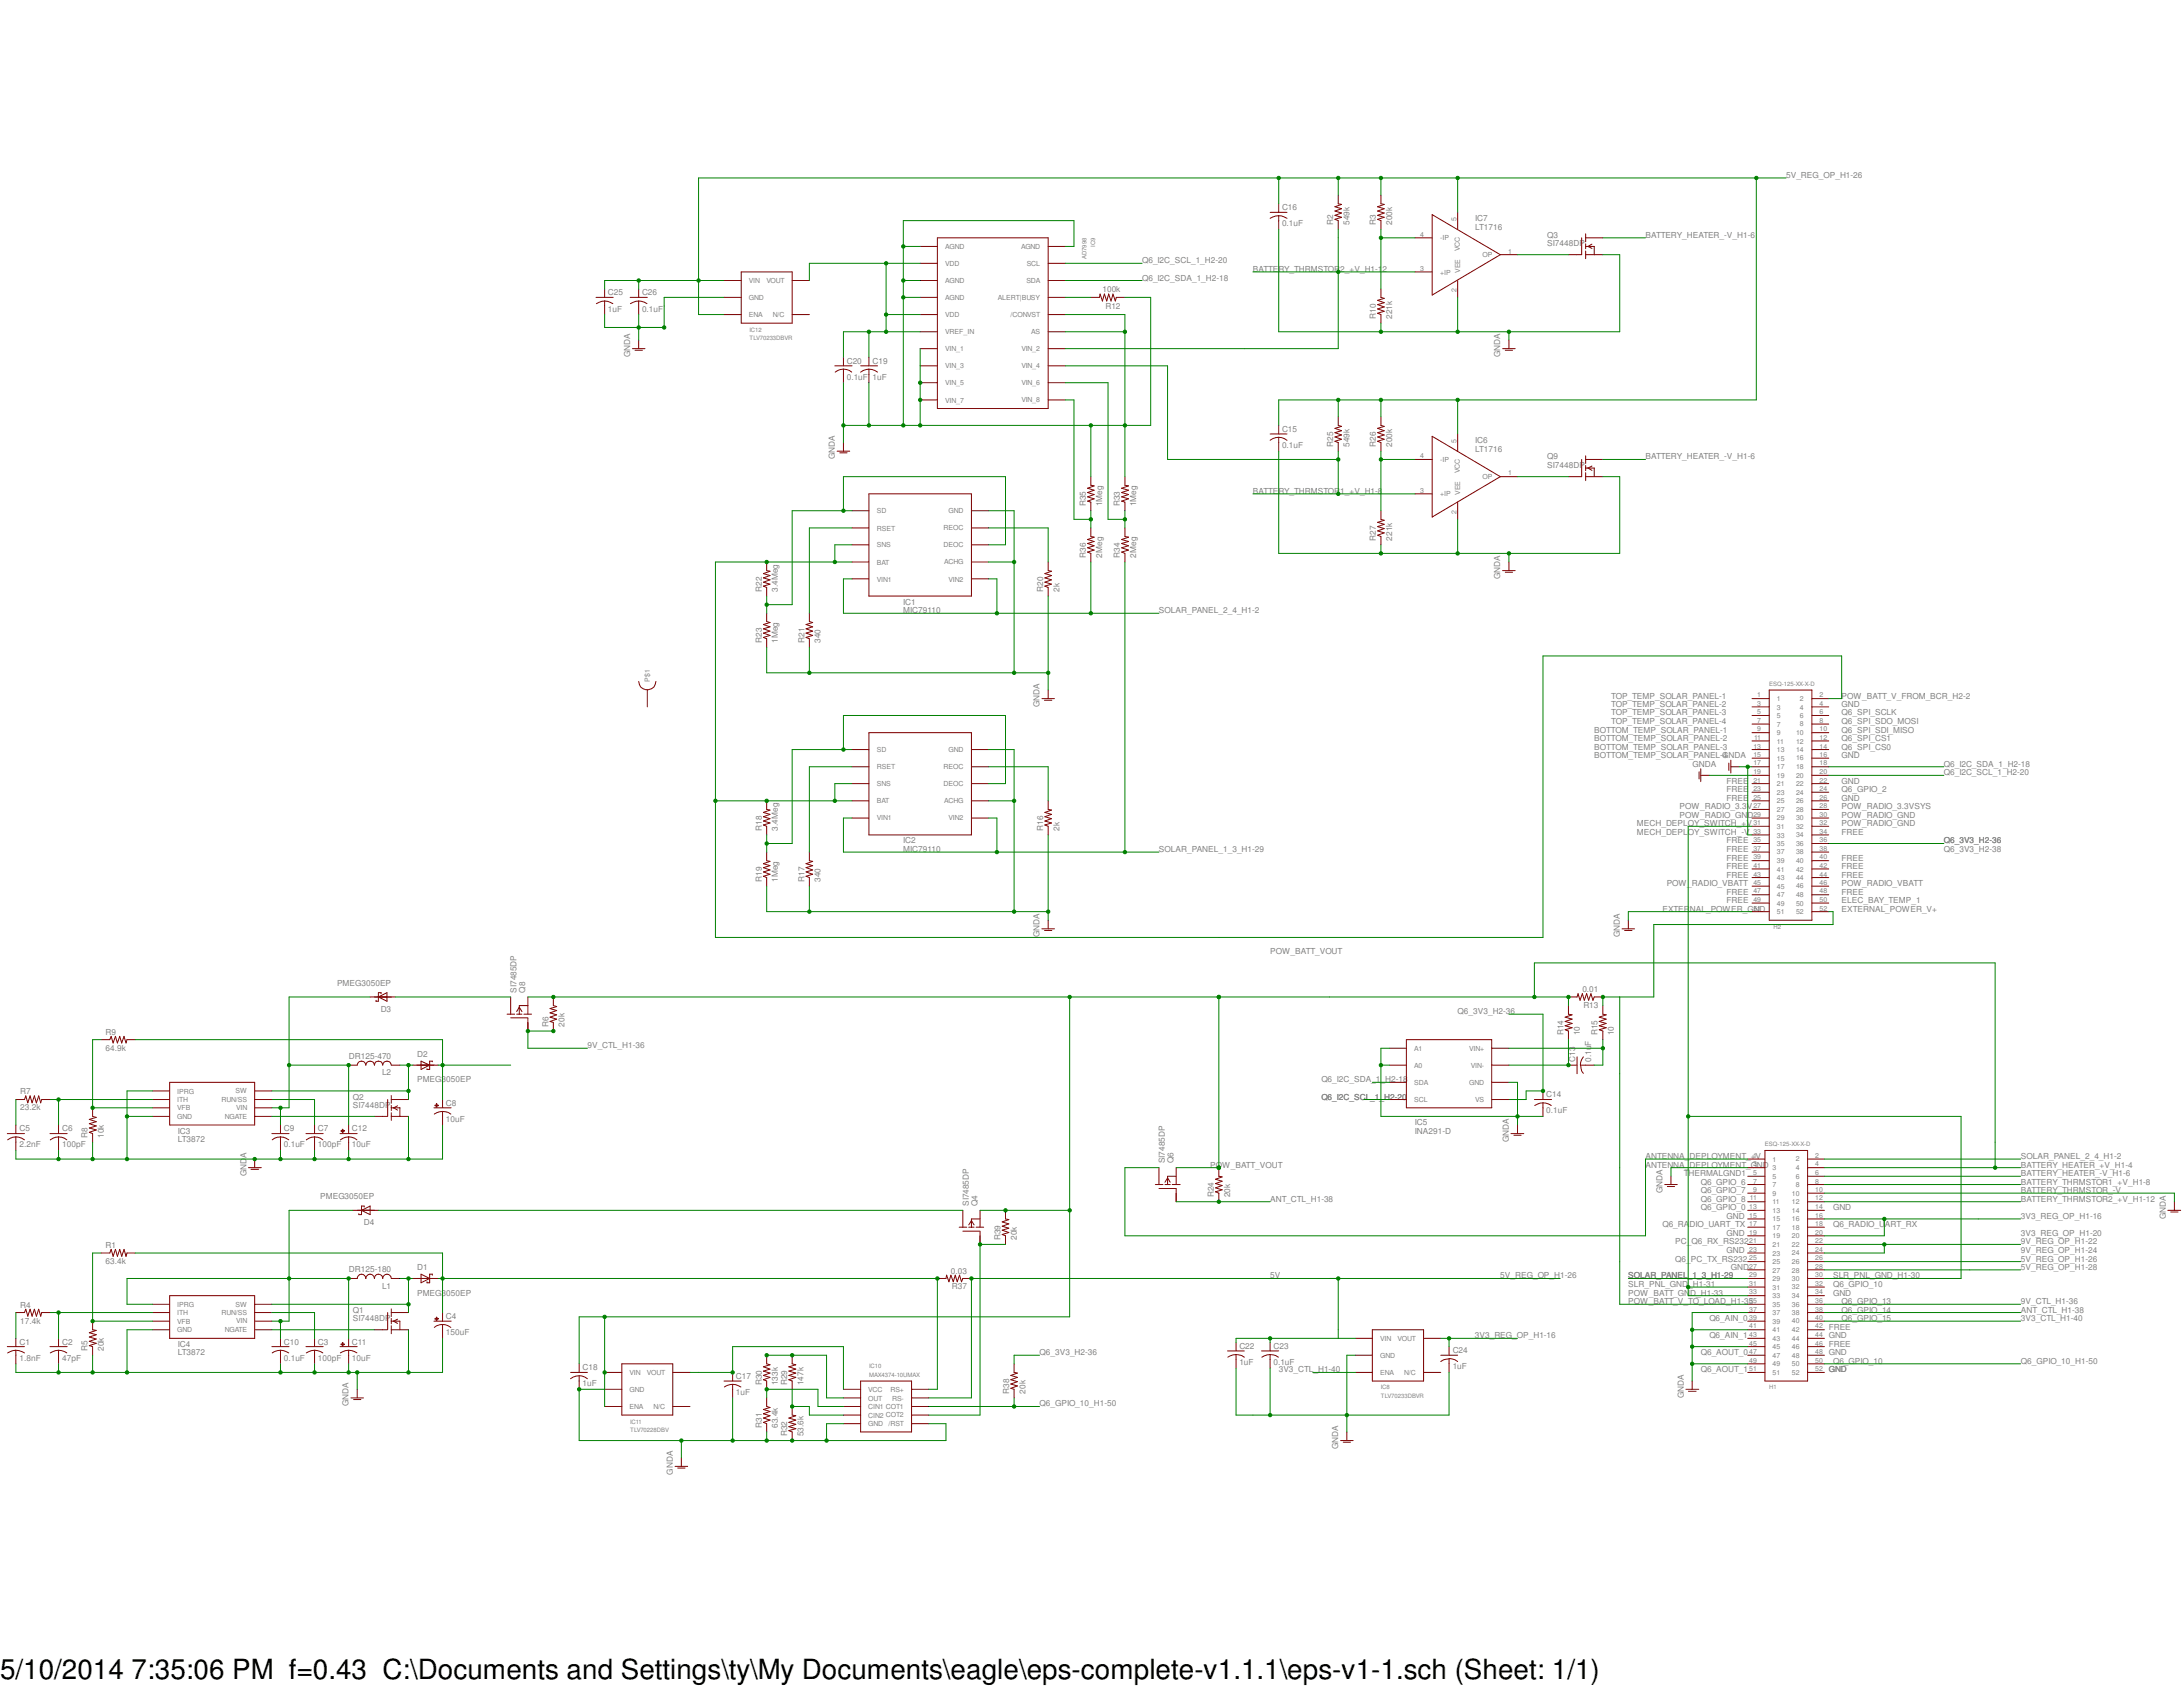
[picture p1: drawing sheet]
<svg xmlns="http://www.w3.org/2000/svg" width="279mm" height="216mm" viewBox="0 0 279 216" stroke-linecap="round" stroke-linejoin="round" font-family="sans-serif">
<defs><g id="words">
<text font-size="3.6" x="0" y="214.9">5/10/2014 7:35:06 PM f=0.43 C:\Documents and Settings\ty\My Documents\eagle\eps-complete-v1.1.1\eps-v1-1.sch (Sheet: 1/1)</text>
<g font-size="1.1" fill="#808080">
<text x="228.6" y="22.8">5V_REG_OP_H1-26</text>
<text x="164.1" y="29">0.1uF</text>
<text x="164.1" y="26.9">C16</text>
<text x="170.6" y="28.8" transform="rotate(-90 170.6 28.8)">R2</text>
<text x="172.7" y="28.8" transform="rotate(-90 172.7 28.8)">549k</text>
<text x="176.1" y="28.8" transform="rotate(-90 176.1 28.8)">R3</text>
<text x="178.2" y="28.8" transform="rotate(-90 178.2 28.8)">200k</text>
<text x="188.8" y="29.4">LT1716</text>
<text x="188.8" y="28.3">IC7</text>
<text x="146.2" y="33.7">Q6_I2C_SCL_1_H2-20</text>
<text x="146.2" y="35.9">Q6_I2C_SDA_1_H2-18</text>
<text x="160.4" y="34.8">BATTERY_THRMSTOR2_+V_H1-12</text>
<text x="198" y="31.5">SI7448DP</text>
<text x="198" y="30.4">Q3</text>
<text x="210.6" y="30.4">BATTERY_HEATER_-V_H1-6</text>
<text x="77.8" y="39.9">1uF</text>
<text x="77.8" y="37.8">C25</text>
<text x="82.2" y="37.8">C26</text>
<text x="82.2" y="39.9">0.1uF</text>
<text x="141.1" y="37.4">100k</text>
<text x="141.5" y="39.5">R12</text>
<text x="176.1" y="40.8" transform="rotate(-90 176.1 40.8)">R10</text>
<text x="178.2" y="40.8" transform="rotate(-90 178.2 40.8)">221k</text>
<text x="80.6" y="45.7" transform="rotate(-90 80.6 45.7)">GNDA</text>
<text x="108.4" y="46.5">C20</text>
<text x="111.7" y="46.5">C19</text>
<text x="192" y="45.7" transform="rotate(-90 192 45.7)">GNDA</text>
<text x="108.4" y="48.6">0.1uF 1uF</text>
<text x="106.8" y="58.8" transform="rotate(-90 106.8 58.8)">GNDA</text>
<text x="164.1" y="57.4">0.1uF</text>
<text x="164.1" y="55.3">C15</text>
<text x="170.6" y="57.2" transform="rotate(-90 170.6 57.2)">R25</text>
<text x="172.7" y="57.2" transform="rotate(-90 172.7 57.2)">549k</text>
<text x="176.1" y="57.2" transform="rotate(-90 176.1 57.2)">R26</text>
<text x="178.2" y="57.2" transform="rotate(-90 178.2 57.2)">200k</text>
<text x="188.8" y="57.8">LT1716</text>
<text x="188.8" y="56.7">IC6</text>
<text x="198" y="59.9">SI7448DP</text>
<text x="198" y="58.8">Q9</text>
<text x="210.6" y="58.8">BATTERY_HEATER_-V_H1-6</text>
<text x="139" y="64.8" transform="rotate(-90 139 64.8)">R35</text>
<text x="141.1" y="64.8" transform="rotate(-90 141.1 64.8)">1Meg</text>
<text x="143.3" y="64.8" transform="rotate(-90 143.3 64.8)">R33</text>
<text x="145.4" y="64.8" transform="rotate(-90 145.4 64.8)">1Meg</text>
<text x="160.4" y="63.2">BATTERY_THRMSTOR1_+V_H1-8</text>
<text x="139" y="71.4" transform="rotate(-90 139 71.4)">R36</text>
<text x="141.1" y="71.4" transform="rotate(-90 141.1 71.4)">2Meg</text>
<text x="143.3" y="71.4" transform="rotate(-90 143.3 71.4)">R34</text>
<text x="145.4" y="71.4" transform="rotate(-90 145.4 71.4)">2Meg</text>
<text x="176.1" y="69.2" transform="rotate(-90 176.1 69.2)">R27</text>
<text x="178.2" y="69.2" transform="rotate(-90 178.2 69.2)">221k</text>
<text x="97.5" y="75.7" transform="rotate(-90 97.5 75.7)">R22</text>
<text x="99.6" y="75.7" transform="rotate(-90 99.6 75.7)">3.4Meg</text>
<text x="115.6" y="77.4">IC1</text>
<text x="133.5" y="75.7" transform="rotate(-90 133.5 75.7)">R20</text>
<text x="135.6" y="75.7" transform="rotate(-90 135.6 75.7)">2k</text>
<text x="192" y="74.1" transform="rotate(-90 192 74.1)">GNDA</text>
<text x="97.5" y="82.3" transform="rotate(-90 97.5 82.3)">R23</text>
<text x="99.6" y="82.3" transform="rotate(-90 99.6 82.3)">1Meg</text>
<text x="103" y="82.3" transform="rotate(-90 103 82.3)">R21</text>
<text x="105" y="82.3" transform="rotate(-90 105 82.3)">340</text>
<text x="115.6" y="78.5">MIC79110</text>
<text x="148.3" y="78.5">SOLAR_PANEL_2_4_H1-2</text>
<text x="206.2" y="89.4">TOP_TEMP_SOLAR_PANEL-1</text>
<text x="235.7" y="89.4">POW_BATT_V_FROM_BCR_H2-2</text>
<text x="133.1" y="90.5" transform="rotate(-90 133.1 90.5)">GNDA</text>
<text x="204" y="93.8">BOTTOM_TEMP_SOLAR_PANEL-1</text>
<text x="204" y="94.8">BOTTOM_TEMP_SOLAR_PANEL-2</text>
<text x="204" y="95.9">BOTTOM_TEMP_SOLAR_PANEL-3</text>
<text x="206.2" y="92.7">TOP_TEMP_SOLAR_PANEL-4</text>
<text x="206.2" y="91.6">TOP_TEMP_SOLAR_PANEL-3</text>
<text x="206.2" y="90.5">TOP_TEMP_SOLAR_PANEL-2</text>
<text x="235.7" y="91.6">Q6_SPI_SCLK</text>
<text x="235.7" y="92.7">Q6_SPI_SDO_MOSI</text>
<text x="235.7" y="93.8">Q6_SPI_SDI_MISO</text>
<text x="235.7" y="94.8">Q6_SPI_CS1</text>
<text x="235.7" y="95.9">Q6_SPI_CS0</text>
<text x="235.7" y="90.5">GND</text>
<text x="204" y="97">BOTTOM_TEMP_SOLAR_PANEL-4</text>
<text x="216.6" y="98.1">GNDA</text>
<text x="220.4" y="97">GNDA</text>
<text x="221" y="100.3">FREE</text>
<text x="221" y="101.4">FREE</text>
<text x="235.7" y="97">GND</text>
<text x="235.7" y="100.3">GND</text>
<text x="235.7" y="101.4">Q6_GPIO_2</text>
<text x="248.8" y="98.1">Q6_I2C_SDA_1_H2-18</text>
<text x="248.8" y="99.2">Q6_I2C_SCL_1_H2-20</text>
<text x="97.5" y="106.3" transform="rotate(-90 97.5 106.3)">R18</text>
<text x="99.6" y="106.3" transform="rotate(-90 99.6 106.3)">3.4Meg</text>
<text x="115.6" y="107.9">IC2</text>
<text x="133.5" y="106.3" transform="rotate(-90 133.5 106.3)">R16</text>
<text x="135.6" y="106.3" transform="rotate(-90 135.6 106.3)">2k</text>
<text x="209.5" y="106.8">MECH_DEPLOY_SWITCH_-V</text>
<text x="209.5" y="105.7">MECH_DEPLOY_SWITCH_+V</text>
<text x="215" y="103.6">POW_RADIO_3.3V</text>
<text x="215" y="104.7">POW_RADIO_GND</text>
<text x="221" y="102.5">FREE</text>
<text x="221" y="107.9">FREE</text>
<text x="235.7" y="102.5">GND</text>
<text x="235.7" y="103.6">POW_RADIO_3.3VSYS</text>
<text x="235.7" y="104.7">POW_RADIO_GND</text>
<text x="235.7" y="105.7">POW_RADIO_GND</text>
<text x="235.7" y="106.8">FREE</text>
<text x="248.8" y="107.9">Q6_3V3_H2-36</text>
<text x="97.5" y="112.9" transform="rotate(-90 97.5 112.9)">R19</text>
<text x="99.6" y="112.9" transform="rotate(-90 99.6 112.9)">1Meg</text>
<text x="103" y="112.9" transform="rotate(-90 103 112.9)">R17</text>
<text x="105" y="112.9" transform="rotate(-90 105 112.9)">340</text>
<text x="115.6" y="109.1">MIC79110</text>
<text x="148.3" y="109.1">SOLAR_PANEL_1_3_H1-29</text>
<text x="213.3" y="113.4">POW_RADIO_VBATT</text>
<text x="221" y="109.1">FREE</text>
<text x="221" y="110.2">FREE</text>
<text x="221" y="111.2">FREE</text>
<text x="221" y="112.3">FREE</text>
<text x="235.7" y="113.4">POW_RADIO_VBATT</text>
<text x="235.7" y="112.3">FREE</text>
<text x="235.7" y="111.2">FREE</text>
<text x="235.7" y="110.2">FREE</text>
<text x="248.8" y="109.1">Q6_3V3_H2-38</text>
<text x="133.1" y="120" transform="rotate(-90 133.1 120)">GNDA</text>
<text x="207.3" y="120" transform="rotate(-90 207.3 120)">GNDA</text>
<text x="212.8" y="116.7">EXTERNAL_POWER_GND</text>
<text x="221" y="114.5">FREE</text>
<text x="221" y="115.6">FREE</text>
<text x="235.7" y="115.6">ELEC_BAY_TEMP_1</text>
<text x="235.7" y="116.7">EXTERNAL_POWER_V+</text>
<text x="235.7" y="114.5">FREE</text>
<text x="162.6" y="122.1">POW_BATT_VOUT</text>
<text x="43.1" y="126.2">PMEG3050EP</text>
<text x="48.7" y="129.5">D3</text>
<text x="66.1" y="127" transform="rotate(-90 66.1 127)">SI7485DP</text>
<text x="67.2" y="127" transform="rotate(-90 67.2 127)">Q8</text>
<text x="70.2" y="131.4" transform="rotate(-90 70.2 131.4)">R6</text>
<text x="72.3" y="131.4" transform="rotate(-90 72.3 131.4)">20k</text>
<text x="186.6" y="129.8">Q6_3V3_H2-36</text>
<text x="202.5" y="127">0.01</text>
<text x="202.6" y="129">R13</text>
<text x="13.5" y="134.5">64.9k</text>
<text x="13.5" y="132.4">R9</text>
<text x="44.7" y="135.5">DR125-470</text>
<text x="48.9" y="137.6">L2</text>
<text x="53.4" y="135.3">D2</text>
<text x="75.2" y="134.2">9V_CTL_H1-36</text>
<text x="200.1" y="132.5" transform="rotate(-90 200.1 132.5)">R14</text>
<text x="201.6" y="135.9" transform="rotate(-90 201.6 135.9)">C13</text>
<text x="202.2" y="132.5" transform="rotate(-90 202.2 132.5)">10</text>
<text x="203.7" y="135.9" transform="rotate(-90 203.7 135.9)">0.1uF</text>
<text x="204.5" y="132.5" transform="rotate(-90 204.5 132.5)">R15</text>
<text x="206.5" y="132.5" transform="rotate(-90 206.5 132.5)">10</text>
<text x="2.6" y="142.1">23.2k</text>
<text x="2.6" y="140">R7</text>
<text x="45.2" y="141.8">SI7448DP</text>
<text x="45.2" y="140.7">Q2</text>
<text x="53.4" y="138.5">PMEG3050EP</text>
<text x="57.1" y="143.6">10uF</text>
<text x="57.1" y="141.5">C8</text>
<text x="169.1" y="140.7">Q6_I2C_SCL_1_H2-20</text>
<text x="169.1" y="138.5">Q6_I2C_SDA_1_H2-18</text>
<text x="181.1" y="144">IC5</text>
<text x="197.9" y="142.5">0.1uF</text>
<text x="197.9" y="140.4">C14</text>
<text x="2.5" y="146.9">2.2nF</text>
<text x="2.5" y="144.8">C5</text>
<text x="8" y="146.9">100pF</text>
<text x="8" y="144.8">C6</text>
<text x="11.2" y="145.6" transform="rotate(-90 11.2 145.6)">R8</text>
<text x="13.3" y="145.6" transform="rotate(-90 13.3 145.6)">10k</text>
<text x="22.8" y="146.2">LT3872</text>
<text x="22.8" y="145.1">IC3</text>
<text x="36.3" y="146.9">0.1uF</text>
<text x="36.3" y="144.8">C9</text>
<text x="40.7" y="146.9">100pF</text>
<text x="40.7" y="144.8">C7</text>
<text x="45" y="146.9">10uF</text>
<text x="45" y="144.8">C12</text>
<text x="149.1" y="148.9" transform="rotate(-90 149.1 148.9)">SI7485DP</text>
<text x="150.2" y="148.9" transform="rotate(-90 150.2 148.9)">Q6</text>
<text x="154.9" y="149.4">POW_BATT_VOUT</text>
<text x="181.1" y="145.1">INA291-D</text>
<text x="193.1" y="146.2" transform="rotate(-90 193.1 146.2)">GNDA</text>
<text x="210.6" y="148.3">ANTENNA_DEPLOYMENT_+V</text>
<text x="210.6" y="149.4">ANTENNA_DEPLOYMENT_GND</text>
<text x="258.7" y="148.3">SOLAR_PANEL_2_4_H1-2</text>
<text x="258.7" y="149.4">BATTERY_HEATER_+V_H1-4</text>
<text x="31.5" y="150.5" transform="rotate(-90 31.5 150.5)">GNDA</text>
<text x="41" y="153.5">PMEG3050EP</text>
<text x="124" y="154.3" transform="rotate(-90 124 154.3)">SI7485DP</text>
<text x="125.1" y="154.3" transform="rotate(-90 125.1 154.3)">Q4</text>
<text x="155.4" y="153.2" transform="rotate(-90 155.4 153.2)">R24</text>
<text x="157.4" y="153.2" transform="rotate(-90 157.4 153.2)">20k</text>
<text x="162.6" y="153.8">ANT_CTL_H1-38</text>
<text x="212.8" y="152.7" transform="rotate(-90 212.8 152.7)">GNDA</text>
<text x="215.5" y="150.5">THERMALGND1</text>
<text x="217.7" y="151.6">Q6_GPIO_6</text>
<text x="217.7" y="152.7">Q6_GPIO_7</text>
<text x="217.7" y="153.8">Q6_GPIO_8</text>
<text x="217.7" y="154.9">Q6_GPIO_0</text>
<text x="221" y="156">GND</text>
<text x="234.6" y="154.9">GND</text>
<text x="258.7" y="156">3V3_REG_OP_H1-16</text>
<text x="258.7" y="150.5">BATTERY_HEATER_-V_H1-6</text>
<text x="258.7" y="151.6">BATTERY_THRMSTOR1_+V_H1-8</text>
<text x="258.7" y="152.7">BATTERY_THRMSTOR_-V</text>
<text x="258.7" y="153.8">BATTERY_THRMSTOR2_+V_H1-12</text>
<text x="277.2" y="156" transform="rotate(-90 277.2 156)">GNDA</text>
<text x="13.5" y="161.8">63.4k</text>
<text x="13.5" y="159.7">R1</text>
<text x="46.6" y="156.8">D4</text>
<text x="128.1" y="158.7" transform="rotate(-90 128.1 158.7)">R39</text>
<text x="130.1" y="158.7" transform="rotate(-90 130.1 158.7)">20k</text>
<text x="212.8" y="157.1">Q6_RADIO_UART_TX</text>
<text x="214.4" y="159.3">PC_Q6_RX_RS232</text>
<text x="214.4" y="161.5">Q6_PC_TX_RS232</text>
<text x="221" y="158.2">GND</text>
<text x="221" y="160.4">GND</text>
<text x="234.6" y="157.1">Q6_RADIO_UART_RX</text>
<text x="258.7" y="158.2">3V3_REG_OP_H1-20</text>
<text x="258.7" y="161.5">5V_REG_OP_H1-26</text>
<text x="258.7" y="159.3">9V_REG_OP_H1-22</text>
<text x="258.7" y="160.4">9V_REG_OP_H1-24</text>
<text x="2.6" y="167.3">R4</text>
<text x="44.7" y="162.8">DR125-180</text>
<text x="45.2" y="168">Q1</text>
<text x="48.9" y="164.9">L1</text>
<text x="53.4" y="165.8">PMEG3050EP</text>
<text x="53.4" y="162.5">D1</text>
<text x="121.7" y="163">0.03</text>
<text x="121.8" y="165">R37</text>
<text x="162.6" y="163.6">5V</text>
<text x="192" y="163.6">5V_REG_OP_H1-26</text>
<text x="208.4" y="166.9">POW_BATT_V_TO_LOAD_H1-35</text>
<text x="208.4" y="165.8">POW_BATT_GND_H1-33</text>
<text x="208.4" y="163.6">SOLAR_PANEL_1_3_H1-29</text>
<text x="208.4" y="164.7">SLR_PNL_GND_H1-31</text>
<text x="221.5" y="162.5">GND</text>
<text x="234.6" y="163.6">SLR_PNL_GND_H1-30</text>
<text x="234.6" y="164.7">Q6_GPIO_10</text>
<text x="234.6" y="165.8">GND</text>
<text x="235.7" y="168">Q6_GPIO_14</text>
<text x="235.7" y="166.9">Q6_GPIO_13</text>
<text x="258.7" y="162.5">5V_REG_OP_H1-28</text>
<text x="258.7" y="168">ANT_CTL_H1-38</text>
<text x="258.7" y="166.9">9V_CTL_H1-36</text>
<text x="2.5" y="172.1">C1</text>
<text x="2.6" y="169.4">17.4k</text>
<text x="8" y="172.1">C2</text>
<text x="11.2" y="172.9" transform="rotate(-90 11.2 172.9)">R5</text>
<text x="13.3" y="172.9" transform="rotate(-90 13.3 172.9)">20k</text>
<text x="22.8" y="173.4">LT3872</text>
<text x="22.8" y="172.4">IC4</text>
<text x="36.3" y="172.1">C10</text>
<text x="40.7" y="172.1">C3</text>
<text x="45" y="172.1">C11</text>
<text x="45.2" y="169.1">SI7448DP</text>
<text x="57.1" y="170.9">150uF</text>
<text x="57.1" y="168.8">C4</text>
<text x="133.1" y="173.4">Q6_3V3_H2-36</text>
<text x="158.6" y="172.6">C22</text>
<text x="163" y="172.6">C23</text>
<text x="185.9" y="173.2">C24</text>
<text x="188.8" y="171.3">3V3_REG_OP_H1-16</text>
<text x="217.7" y="173.4">Q6_AOUT_0</text>
<text x="218.8" y="169.1">Q6_AIN_0</text>
<text x="218.8" y="171.3">Q6_AIN_1</text>
<text x="234.1" y="172.4">FREE</text>
<text x="234.1" y="171.3">GND</text>
<text x="234.1" y="170.2">FREE</text>
<text x="234.1" y="173.4">GND</text>
<text x="235.7" y="169.1">Q6_GPIO_15</text>
<text x="258.7" y="169.1">3V3_CTL_H1-40</text>
<text x="2.5" y="174.2">1.8nF</text>
<text x="8" y="174.2">47pF</text>
<text x="36.3" y="174.2">0.1uF</text>
<text x="40.7" y="174.2">100pF</text>
<text x="45" y="174.2">10uF</text>
<text x="74.5" y="175.3">C18</text>
<text x="74.5" y="177.4">1uF</text>
<text x="94.2" y="178.5">1uF</text>
<text x="94.2" y="176.4">C17</text>
<text x="97.5" y="177.3" transform="rotate(-90 97.5 177.3)">R30</text>
<text x="99.6" y="177.3" transform="rotate(-90 99.6 177.3)">133k</text>
<text x="100.8" y="177.3" transform="rotate(-90 100.8 177.3)">R29</text>
<text x="102.8" y="177.3" transform="rotate(-90 102.8 177.3)">147k</text>
<text x="129.2" y="178.4" transform="rotate(-90 129.2 178.4)">R38</text>
<text x="131.2" y="178.4" transform="rotate(-90 131.2 178.4)">20k</text>
<text x="158.6" y="174.7">1uF</text>
<text x="163" y="174.7">0.1uF</text>
<text x="163.7" y="175.6">3V3_CTL_H1-40</text>
<text x="185.9" y="175.3">1uF</text>
<text x="215.5" y="178.9" transform="rotate(-90 215.5 178.9)">GNDA</text>
<text x="217.7" y="175.6">Q6_AOUT_1</text>
<text x="234.1" y="175.6">GND</text>
<text x="234.6" y="174.5">Q6_GPIO_10</text>
<text x="258.7" y="174.5">Q6_GPIO_10_H1-50</text>
<text x="44.6" y="180" transform="rotate(-90 44.6 180)">GNDA</text>
<text x="97.5" y="182.8" transform="rotate(-90 97.5 182.8)">R31</text>
<text x="99.6" y="182.8" transform="rotate(-90 99.6 182.8)">63.4k</text>
<text x="100.8" y="183.8" transform="rotate(-90 100.8 183.8)">R32</text>
<text x="102.8" y="183.8" transform="rotate(-90 102.8 183.8)">53.6k</text>
<text x="133.1" y="180">Q6_GPIO_10_H1-50</text>
<text x="171.3" y="185.5" transform="rotate(-90 171.3 185.5)">GNDA</text>
<text x="86.1" y="188.7" transform="rotate(-90 86.1 188.7)">GNDA</text>
</g>
<g font-size=".9" fill="#808080">
<text x="186.4" y="28.3" transform="rotate(-90 186.4 28.3)">5</text>
<text x="121" y="31.8">AGND</text>
<text x="121" y="34">VDD</text>
<text x="130.7" y="31.8">AGND</text>
<text x="131.4" y="34">SCL</text>
<text x="181.8" y="30.3">4</text>
<text x="181.8" y="34.6">3</text>
<text x="184.3" y="30.8">-IP</text>
<text x="184.3" y="35.1">+IP</text>
<text x="186.9" y="32.2" transform="rotate(-90 186.9 32.2)">VCC</text>
<text x="186.9" y="34.9" transform="rotate(-90 186.9 34.9)">VEE</text>
<text x="189.7" y="32.9">OP</text>
<text x="193" y="32.5">1</text>
<text x="95.8" y="36.2">VIN</text>
<text x="95.8" y="38.4">GND</text>
<text x="95.8" y="40.6">ENA</text>
<text x="98.1" y="36.2">VOUT</text>
<text x="98.9" y="40.6">N/C</text>
<text x="121" y="36.2">AGND</text>
<text x="121" y="38.4">AGND</text>
<text x="121" y="40.6">VDD</text>
<text x="127.7" y="38.4">ALERT|BUSY</text>
<text x="129.3" y="40.6">/CONVST</text>
<text x="131.4" y="36.2">SDA</text>
<text x="186.4" y="37.4" transform="rotate(-90 186.4 37.4)">2</text>
<text x="121" y="42.8">VREF_IN</text>
<text x="121" y="45">VIN_1</text>
<text x="121" y="47.2">VIN_3</text>
<text x="130.7" y="47.1">VIN_4</text>
<text x="130.7" y="44.9">VIN_2</text>
<text x="132" y="42.8">AS</text>
<text x="121" y="49.3">VIN_5</text>
<text x="121" y="51.5">VIN_7</text>
<text x="130.7" y="51.5">VIN_8</text>
<text x="130.7" y="49.3">VIN_6</text>
<text x="181.8" y="58.7">4</text>
<text x="184.3" y="59.1">-IP</text>
<text x="186.4" y="56.7" transform="rotate(-90 186.4 56.7)">5</text>
<text x="112.2" y="65.7">SD</text>
<text x="121.4" y="65.7">GND</text>
<text x="181.8" y="63">3</text>
<text x="184.3" y="63.5">+IP</text>
<text x="186.4" y="65.8" transform="rotate(-90 186.4 65.8)">2</text>
<text x="186.9" y="60.5" transform="rotate(-90 186.9 60.5)">VCC</text>
<text x="186.9" y="63.3" transform="rotate(-90 186.9 63.3)">VEE</text>
<text x="189.7" y="61.3">OP</text>
<text x="193" y="60.8">1</text>
<text x="112.2" y="67.9">RSET</text>
<text x="112.2" y="70.1">SNS</text>
<text x="120.8" y="70.1">DEOC</text>
<text x="120.8" y="67.9">REOC</text>
<text x="112.2" y="72.3">BAT</text>
<text x="112.2" y="74.4">VIN1</text>
<text x="120.9" y="72.2">ACHG</text>
<text x="121.4" y="74.4">VIN2</text>
<text x="83.2" y="87.3" transform="rotate(-90 83.2 87.3)">P$1</text>
<text x="224.9" y="89.2">1</text>
<text x="227.4" y="89.7">1</text>
<text x="230.4" y="89.7">2</text>
<text x="232.9" y="89.2">2</text>
<text x="224.4" y="95.8">13</text>
<text x="224.5" y="94.7">11</text>
<text x="224.9" y="90.3">3</text>
<text x="224.9" y="91.4">5</text>
<text x="224.9" y="92.5">7</text>
<text x="224.9" y="93.6">9</text>
<text x="227.4" y="90.8">3</text>
<text x="227.4" y="91.9">5</text>
<text x="227.4" y="93">7</text>
<text x="227.4" y="94.1">9</text>
<text x="227.4" y="95.2">11</text>
<text x="229.9" y="94.1">10</text>
<text x="229.9" y="95.2">12</text>
<text x="230.4" y="90.8">4</text>
<text x="230.4" y="91.9">6</text>
<text x="230.4" y="93">8</text>
<text x="232.9" y="90.3">4</text>
<text x="232.9" y="91.4">6</text>
<text x="232.9" y="92.5">8</text>
<text x="232.9" y="93.6">10</text>
<text x="232.9" y="94.7">12</text>
<text x="232.9" y="95.8">14</text>
<text x="112.2" y="96.3">SD</text>
<text x="112.2" y="98.5">RSET</text>
<text x="112.2" y="100.6">SNS</text>
<text x="120.8" y="100.6">DEOC</text>
<text x="120.8" y="98.4">REOC</text>
<text x="121.4" y="96.3">GND</text>
<text x="224.4" y="96.9">15</text>
<text x="224.4" y="98">17</text>
<text x="224.4" y="99.1">19</text>
<text x="224.4" y="100.2">21</text>
<text x="224.4" y="101.3">23</text>
<text x="227.4" y="96.3">13</text>
<text x="227.4" y="97.4">15</text>
<text x="227.4" y="98.5">17</text>
<text x="227.4" y="99.5">19</text>
<text x="227.4" y="100.6">21</text>
<text x="227.4" y="101.7">23</text>
<text x="229.9" y="96.3">14</text>
<text x="229.9" y="97.3">16</text>
<text x="229.9" y="98.4">18</text>
<text x="229.9" y="99.5">20</text>
<text x="229.9" y="100.6">22</text>
<text x="229.9" y="101.7">24</text>
<text x="232.9" y="96.9">16</text>
<text x="232.9" y="98">18</text>
<text x="232.9" y="99.1">20</text>
<text x="232.9" y="100.2">22</text>
<text x="232.9" y="101.3">24</text>
<text x="112.2" y="102.8">BAT</text>
<text x="112.2" y="105">VIN1</text>
<text x="120.9" y="102.8">ACHG</text>
<text x="121.4" y="105">VIN2</text>
<text x="224.4" y="102.3">25</text>
<text x="224.4" y="103.4">27</text>
<text x="224.4" y="104.5">29</text>
<text x="224.4" y="105.6">31</text>
<text x="224.4" y="106.7">33</text>
<text x="224.4" y="107.8">35</text>
<text x="227.4" y="102.8">25</text>
<text x="227.4" y="103.9">27</text>
<text x="227.4" y="105">29</text>
<text x="227.4" y="106.1">31</text>
<text x="227.4" y="107.2">33</text>
<text x="229.9" y="102.8">26</text>
<text x="229.9" y="103.9">28</text>
<text x="229.9" y="105">30</text>
<text x="229.9" y="106.1">32</text>
<text x="229.9" y="107.1">34</text>
<text x="232.9" y="102.3">26</text>
<text x="232.9" y="103.4">28</text>
<text x="232.9" y="104.5">30</text>
<text x="232.9" y="105.6">32</text>
<text x="232.9" y="106.7">34</text>
<text x="232.9" y="107.8">36</text>
<text x="224.4" y="108.9">37</text>
<text x="224.4" y="110">39</text>
<text x="224.4" y="111.1">41</text>
<text x="224.4" y="112.2">43</text>
<text x="224.4" y="113.2">45</text>
<text x="227.4" y="108.3">35</text>
<text x="227.4" y="109.3">37</text>
<text x="227.4" y="110.4">39</text>
<text x="227.4" y="111.5">41</text>
<text x="227.4" y="112.6">43</text>
<text x="227.4" y="113.7">45</text>
<text x="229.9" y="108.2">36</text>
<text x="229.9" y="109.3">38</text>
<text x="229.9" y="110.4">40</text>
<text x="229.9" y="111.5">42</text>
<text x="229.9" y="112.6">44</text>
<text x="229.9" y="113.7">46</text>
<text x="232.9" y="108.9">38</text>
<text x="232.9" y="110">40</text>
<text x="232.9" y="111.1">42</text>
<text x="232.9" y="112.2">44</text>
<text x="232.9" y="113.2">46</text>
<text x="224.4" y="114.3">47</text>
<text x="224.4" y="115.4">49</text>
<text x="224.4" y="116.5">51</text>
<text x="227.4" y="114.8">47</text>
<text x="227.4" y="115.9">49</text>
<text x="227.4" y="117">51</text>
<text x="229.9" y="114.8">48</text>
<text x="229.9" y="115.9">50</text>
<text x="229.9" y="117">52</text>
<text x="232.9" y="114.3">48</text>
<text x="232.9" y="115.4">50</text>
<text x="232.9" y="116.5">52</text>
<text x="181" y="134.5">A1</text>
<text x="181" y="136.7">A0</text>
<text x="188" y="134.5">VIN+</text>
<text x="188.3" y="136.7">VIN-</text>
<text x="22.7" y="140">IPRG</text>
<text x="22.7" y="141">ITH</text>
<text x="22.7" y="142.1">VFB</text>
<text x="22.7" y="143.2">GND</text>
<text x="28.4" y="141">RUN/SS</text>
<text x="28.8" y="143.2">NGATE</text>
<text x="30.1" y="139.9">SW</text>
<text x="30.2" y="142.1">VIN</text>
<text x="181" y="138.9">SDA</text>
<text x="181" y="141">SCL</text>
<text x="188" y="138.8">GND</text>
<text x="188.8" y="141">VS</text>
<text x="224.4" y="148.2">1</text>
<text x="224.4" y="149.3">3</text>
<text x="226.9" y="148.7">1</text>
<text x="226.9" y="149.8">3</text>
<text x="229.8" y="148.6">2</text>
<text x="229.8" y="149.7">4</text>
<text x="232.3" y="148.2">2</text>
<text x="232.3" y="149.3">4</text>
<text x="223.9" y="154.7">13</text>
<text x="223.9" y="155.8">15</text>
<text x="223.9" y="153.6">11</text>
<text x="224.4" y="150.4">5</text>
<text x="224.4" y="151.5">7</text>
<text x="224.4" y="152.6">9</text>
<text x="226.9" y="150.8">5</text>
<text x="226.9" y="151.9">7</text>
<text x="226.9" y="153">9</text>
<text x="226.9" y="154.1">11</text>
<text x="226.9" y="155.2">13</text>
<text x="229.3" y="153">10</text>
<text x="229.3" y="154.1">12</text>
<text x="229.3" y="155.2">14</text>
<text x="229.8" y="150.8">6</text>
<text x="229.8" y="151.9">8</text>
<text x="232.3" y="150.4">6</text>
<text x="232.3" y="151.5">8</text>
<text x="232.3" y="152.6">10</text>
<text x="232.3" y="153.6">12</text>
<text x="232.3" y="154.7">14</text>
<text x="232.3" y="155.8">16</text>
<text x="223.9" y="156.9">17</text>
<text x="223.9" y="158">19</text>
<text x="223.9" y="159.1">21</text>
<text x="223.9" y="160.2">23</text>
<text x="223.9" y="161.3">25</text>
<text x="226.9" y="156.3">15</text>
<text x="226.9" y="157.4">17</text>
<text x="226.9" y="158.5">19</text>
<text x="226.9" y="159.6">21</text>
<text x="226.9" y="160.7">23</text>
<text x="226.9" y="161.8">25</text>
<text x="229.3" y="156.3">16</text>
<text x="229.3" y="157.4">18</text>
<text x="229.3" y="158.5">20</text>
<text x="229.3" y="159.6">22</text>
<text x="229.3" y="160.7">24</text>
<text x="229.3" y="161.8">26</text>
<text x="232.3" y="156.9">18</text>
<text x="232.3" y="158">20</text>
<text x="232.3" y="159.1">22</text>
<text x="232.3" y="160.2">24</text>
<text x="232.3" y="161.3">26</text>
<text x="22.7" y="167.2">IPRG</text>
<text x="30.1" y="167.2">SW</text>
<text x="223.9" y="162.4">27</text>
<text x="223.9" y="163.5">29</text>
<text x="223.9" y="164.5">31</text>
<text x="223.9" y="165.7">33</text>
<text x="223.9" y="166.8">35</text>
<text x="223.9" y="167.9">37</text>
<text x="226.9" y="162.9">27</text>
<text x="226.9" y="164">29</text>
<text x="226.9" y="165.1">31</text>
<text x="226.9" y="166.2">33</text>
<text x="226.9" y="167.2">35</text>
<text x="229.3" y="162.9">28</text>
<text x="229.3" y="163.9">30</text>
<text x="229.3" y="165">32</text>
<text x="229.3" y="166.1">34</text>
<text x="229.3" y="167.2">36</text>
<text x="232.3" y="162.4">28</text>
<text x="232.3" y="163.5">30</text>
<text x="232.3" y="164.5">32</text>
<text x="232.3" y="165.7">34</text>
<text x="232.3" y="166.8">36</text>
<text x="232.3" y="167.9">38</text>
<text x="22.7" y="168.3">ITH</text>
<text x="22.7" y="169.4">VFB</text>
<text x="22.7" y="170.5">GND</text>
<text x="28.4" y="168.3">RUN/SS</text>
<text x="28.8" y="170.5">NGATE</text>
<text x="30.2" y="169.4">VIN</text>
<text x="176.7" y="171.6">VIN</text>
<text x="176.7" y="173.8">GND</text>
<text x="178.9" y="171.6">VOUT</text>
<text x="223.9" y="169">39</text>
<text x="223.9" y="170">41</text>
<text x="223.9" y="171.1">43</text>
<text x="223.9" y="172.2">45</text>
<text x="223.9" y="173.3">47</text>
<text x="226.9" y="168.3">37</text>
<text x="226.9" y="169.4">39</text>
<text x="226.9" y="170.5">41</text>
<text x="226.9" y="171.6">43</text>
<text x="226.9" y="172.7">45</text>
<text x="226.9" y="173.8">47</text>
<text x="229.3" y="168.3">38</text>
<text x="229.3" y="169.4">40</text>
<text x="229.3" y="170.5">42</text>
<text x="229.3" y="171.6">44</text>
<text x="229.3" y="172.7">46</text>
<text x="229.3" y="173.8">48</text>
<text x="232.3" y="169">40</text>
<text x="232.3" y="170">42</text>
<text x="232.3" y="171.1">44</text>
<text x="232.3" y="172.2">46</text>
<text x="232.3" y="173.3">48</text>
<text x="80.6" y="176">VIN</text>
<text x="80.6" y="178.1">GND</text>
<text x="82.8" y="175.9">VOUT</text>
<text x="111.1" y="179.2">OUT</text>
<text x="111.1" y="178.1">VCC</text>
<text x="114" y="178.1">RS+</text>
<text x="114.2" y="179.2">RS-</text>
<text x="176.7" y="176">ENA</text>
<text x="179.7" y="175.9">N/C</text>
<text x="223.9" y="174.4">49</text>
<text x="223.9" y="175.5">51</text>
<text x="226.9" y="174.9">49</text>
<text x="226.9" y="176">51</text>
<text x="229.3" y="174.8">50</text>
<text x="229.3" y="175.9">52</text>
<text x="232.3" y="174.4">50</text>
<text x="232.3" y="175.5">52</text>
<text x="80.6" y="180.3">ENA</text>
<text x="83.7" y="180.3">N/C</text>
<text x="111.1" y="180.3">CIN1 COT1</text>
<text x="111.1" y="181.4">CIN2 COT2</text>
<text x="111.1" y="182.5">GND</text>
<text x="113.7" y="182.5">/RST</text>
</g>
<g font-size=".8" fill="#808080">
<text x="139.1" y="33.1" transform="rotate(-90 139.1 33.1)">AD7998</text>
<text x="140.2" y="31.6" transform="rotate(-90 140.2 31.6)">IC9</text>
<text x="95.9" y="42.5">IC12</text>
<text x="95.9" y="43.5">TLV70233DBVR</text>
<text x="226.4" y="87.8">ESQ-125-XX-X-D</text>
<text x="227" y="118.9">H2</text>
<text x="225.9" y="146.7">ESQ-125-XX-X-D</text>
<text x="111.3" y="176.2">MAX4374-10UMAX</text>
<text x="111.3" y="175.1">IC10</text>
<text x="176.7" y="178.9">TLV70233DBVR</text>
<text x="176.7" y="177.8">IC8</text>
<text x="226.4" y="177.8">H1</text>
<text x="80.6" y="183.3">TLV70228DBV</text>
<text x="80.6" y="182.2">IC11</text>
</g>
</g></defs>
<g fill="none" stroke="#800000" stroke-width=".13">
<path d="M98.1 71.9v1.1l.5 .1-.9 .3 .9 .3-.9 .3 .9 .2-.9 .3 .9 .3-.9 .2 .4 .2v1.1M98.1 78.5v1l.5 .2-.9 .2 .9 .3-.9 .3 .9 .3-.9 .2 .9 .3-.9 .3 .4 .1v1.1M103.6 78.5v1l.4 .2-.8 .2 .8 .3-.8 .3 .8 .3-.8 .2 .8 .3-.8 .3 .4 .1v1.1M109.1 65.4h2.1M109.1 67.6h2.1M109.1 69.7h2.1M109.1 71.9h2.1M109.1 74.1h2.1M111.2 63.2h13.1v13.1h-13.1zM124.3 65.4h2.2M124.3 67.6h2.2M124.3 69.7h2.2"/>
<path d="M124.3 71.9h2.2M124.3 74.1h2.2M134.2 71.9v1.1l.4 .1-.9 .3 .9 .3-.9 .3 .9 .2-.9 .3 .9 .3-.9 .2 .5 .2v1.1M109.1 95.9h2.1M109.1 98.1h2.1M111.2 93.8h13.1v13h-13.1zM124.3 95.9h2.2M124.3 98.1h2.2M133.3 89.4h1.7M133.7 89.6h.9M134.2 88.3v1.1M98.1 102.5v1.1l.5 .1-.9 .3 .9 .2-.9 .3 .9 .3-.9 .3 .9 .2-.9 .3 .4 .1v1.1"/>
<path d="M98.1 109.1v1.1h.5l-.9 .3 .9 .3-.9 .2 .9 .3-.9 .3 .9 .3-.9 .2 .4 .2v1.1M103.6 109.1v1.1h.4l-.8 .3 .8 .3-.8 .2 .8 .3-.8 .3 .8 .3-.8 .2 .4 .2v1.1M109.1 100.3h2.1M109.1 102.5h2.1M109.1 104.7h2.1M124.3 100.3h2.2M124.3 102.5h2.2M124.3 104.7h2.2M133.3 118.9h1.7M133.7 119.1h.9M134.2 102.5v1.1l.4 .1-.9 .3 .9 .2-.9 .3 .9 .3-.9 .3 .9 .2-.9 .3 .5 .1v1.1M134.2 117.8v1.1"/>
<path d="M13 133.1h1.1l.1-.5 .3 .9 .3-.9 .2 .9 .3-.9 .3 .9 .3-.9 .2 .9 .2-.4h1M2 140.7h1.1l.2-.4 .3 .8 .3-.8 .2 .8 .3-.8 .3 .8 .3-.8 .2 .8 .1-.4h1.1M11.9 141.8v1.1l.4 .1-.9 .3 .9 .3-.9 .2 .9 .3-.9 .3 .9 .2-.9 .3 .5 .2v1.1M156 149.4v1.1l.4 .1-.8 .3 .8 .3-.8 .3 .8 .2-.8 .3 .8 .3-.8 .2 .4 .2v1.1M.9 172.3h2.2M2 172.8h.4l.7 .3M2 172.8h-.3l-.7 .3M2 168h1.1l.2-.4 .3 .8 .3-.8 .2 .8 .3-.8 .3 .8 .3-.8 .2 .8 .1-.4h1.1M2 171.3v1M2 172.8v1.7M6.4 172.3h2.2M7.5 172.8h.4l.7 .3"/>
<path d="M7.5 172.8h-.4l-.7 .3M7.5 171.3v1M7.5 172.8v1.7M11.9 169.1v1.1l.4 .1-.9 .3 .9 .2-.9 .3 .9 .3-.9 .3 .9 .2-.9 .3 .5 .1v1.1M13 160.4h1.1l.1-.5 .3 .9 .3-.9 .2 .9 .3-.9 .3 .9 .3-.9 .2 .9 .2-.4h1M39.2 172.3h2.2M40.3 172.8h.3l.7 .3M40.3 172.8h-.4l-.7 .3M40.3 171.3v1M40.3 172.8v1.7M44.9 178.9h1.6M45.3 179.1h.9"/>
<path d="M45.7 177.8v1.1M55.5 169.1h2.2M56.6 169.5h.4l.7 .4M56.6 169.5l-.7 .2-.3 .2M56.6 169.5v.7"/>
</g>
<path d="M55.7 168.7h.4v.1h-.4z" fill-rule="evenodd" fill="#800000"/>
<path d="M55.7 168.7h.4v.1h-.4z" fill="none" stroke="#800000" stroke-width=".13"/>
<path d="M55.8 168.6h.1v.4h-.1z" fill-rule="evenodd" fill="#800000"/>
<g fill="none" stroke="#800000" stroke-width=".13">
<path d="M.9 145.1h2.2M2 145.5l.8 .2 .3 .2M2 145.5h-.3l-.7 .4M2 144v1.1M2 145.5v1.7M6.4 145.1h2.2M7.5 145.5l.8 .2 .3 .2M7.5 145.5h-.4l-.7 .4M7.5 144v1.1M7.5 145.5v1.7M39.2 145.1h2.2M40.3 145.5l.7 .2 .3 .2"/>
<path d="M40.3 145.5h-.4l-.7 .4M40.3 144v1.1M40.3 145.5v1.7M47.9 142.9h1.7M49.6 140.7v2.2M50.1 140.2v1M50.1 141.5v.6M50.1 142.4v1M50.1 141.8h1.1v1.1M50.1 142.9h2.2M50.1 140.7h2.2M50.9 141.5l-.5 .3 .5 .3"/>
<path d="M55.5 141.8h2.2M56.6 142.2l.8 .2 .3 .2M56.6 142.2l-.3 .1-.7 .3M56.6 142.2v.7M47.9 170.2h1.7M49.6 168v2.2M50.1 170.2h2.2M50.1 167.5v1M50.1 168.7v.7M50.1 169.7v1M50.1 169.1h1.1v1.1M50.1 168h2.2"/>
<path d="M50.9 168.8l-.5 .3 .5 .3M55.8 168.6h.1v.4h-.1zM56.6 168v1.1M56.6 170.2v1.1"/>
</g>
<path d="M55.7 141.4h.4v.1h-.4z" fill-rule="evenodd" fill="#800000"/>
<path d="M55.7 141.4h.4v.1h-.4z" fill="none" stroke="#800000" stroke-width=".13"/>
<path d="M55.8 141.3h.1v.4h-.1z" fill-rule="evenodd" fill="#800000"/>
<g fill="none" stroke="#800000" stroke-width=".13">
<path d="M44.6 136.3h1.1a.55 .55 0 0 1 .6-.5 .55 .55 0 0 1 .5 .5 .55 .55 0 0 1 .6-.5 .55 .55 0 0 1 .5 .5 .53 .53 0 0 1 .6-.5 .53 .53 0 0 1 .5 .5 .55 .55 0 0 1 .5-.5 .55 .55 0 0 1 .6 .5h1.1M64.9 129.8h1M65.4 130.3h2.2M65.4 127.6v2.2M66.1 129.8h.7M66.1 129.5l.4-.6 .3 .6M67.1 129.8h.9M67.6 127.6v2.2M67.6 130.3v1.7M67.6 128.7h-1.1v1.1M70.8 127.6v1.1l.4 .1-.8 .3 .8 .2-.8 .3 .8 .3-.8 .3 .8 .2-.8 .3 .4 .2v1.1M34.8 145.1h2.2"/>
<path d="M35.9 145.5h.4l.7 .4M35.9 145.5l-.8 .2-.3 .2M35.9 144v1.1M35.9 145.5v1.7M55.8 141.3h.1v.4h-.1zM56.6 140.7v1.1M56.6 142.9v1.1M147.9 151.6h.9M148.3 152.1h2.2M148.3 149.4v2.2M149.1 151.6h.7M149.1 151.3l.3-.6 .4 .6"/>
<path d="M150 151.6h1M150.5 149.4v2.2M150.5 152.1v1.7M150.5 150.5h-1.1v1.1M34.8 172.3h2.2M35.9 172.8h.4l.7 .3M35.9 172.8h-.4l-.7 .3M35.9 171.3v1M35.9 172.8v1.7M43.5 172.3h2.2M44.6 163.6h1.1a.55 .55 0 0 1 .6-.5 .55 .55 0 0 1 .5 .5 .55 .55 0 0 1 .6-.5 .55 .55 0 0 1 .5 .5 .53 .53 0 0 1 .6-.5 .53 .53 0 0 1 .5 .5 .55 .55 0 0 1 .5-.5 .55 .55 0 0 1 .6 .5h1.1M44.6 172.8h.4l.7 .3"/>
<path d="M44.6 172.8h-.4l-.6 .3M44.6 172.8v.6"/>
</g>
<path d="M43.6 172h.5v.1h-.5z" fill-rule="evenodd" fill="#800000"/>
<path d="M43.6 172h.5v.1h-.5z" fill="none" stroke="#800000" stroke-width=".13"/>
<path d="M43.8 171.8h.1v.5h-.1z" fill-rule="evenodd" fill="#800000"/>
<path d="M43.5 145.1h2.2M44.6 145.5l.8 .2 .3 .2M44.6 145.5h-.4l-.6 .4M44.6 145.5v.7M43.8 171.8h.1v.5h-.1zM44.6 171.3v1M44.6 173.4v1.1" fill="none" stroke="#800000" stroke-width=".13"/>
<path d="M43.6 144.7h.5v.1h-.5z" fill-rule="evenodd" fill="#800000"/>
<path d="M43.6 144.7h.5v.1h-.5z" fill="none" stroke="#800000" stroke-width=".13"/>
<path d="M43.8 144.5h.1v.4h-.1z" fill-rule="evenodd" fill="#800000"/>
<g fill="none" stroke="#800000" stroke-width=".13">
<path d="M76.3 38.1h2.2M77.4 38.5l.4 .1 .6 .3M77.4 38.5l-.4 .1-.7 .3M77.4 37v1.1M77.4 38.5v1.8M80.6 38.1h2.2M81.7 38.5l.4 .1 .7 .3M81.7 38.5l-.3 .1-.7 .3M81.7 37v1.1M81.7 38.5v1.8M92.7 35.9h2.2M92.7 38.1h2.2"/>
<path d="M94.9 34.8h6.5v6.6h-6.5zM101.4 35.9h2.2M117.8 31.5h2.2M117.8 33.7h2.2M117.8 35.9h2.2M117.8 38.1h2.2M120 30.4h14.2v21.9h-14.2zM134.2 31.5h2.2M134.2 33.7h2.2M134.2 35.9h2.2M134.2 38.1h2.2M139.6 38.1h1.1l.1-.5 .3 .9 .3-.9 .2 .9 .3-.9 .3 .9 .3-.9 .2 .9 .2-.4h1.1"/>
<path d="M162.6 27.2h2.1M163.7 27.6h.3l.7 .3M163.7 27.6h-.4l-.7 .3M163.7 26.1v1.1M163.7 27.6v1.7M171.3 25v1.1l.4 .1-.8 .3 .8 .2-.8 .3 .8 .3-.8 .3 .8 .2-.8 .3 .4 .1v1.1M176.7 25v1.1l.5 .1-.9 .3 .9 .2-.9 .3 .9 .3-.9 .3 .9 .2-.9 .3 .4 .1v1.1M176.7 37v1.1l.5 .1-.9 .2 .9 .3-.9 .3 .9 .3-.9 .2 .9 .3-.9 .3 .4 .2v1.1M181.1 30.4h2.2M181.1 34.8h2.2M183.3 27.5l8.7 5.1-8.7 5.2zM186.6 27.2v2.1"/>
<path d="M186.6 35.9v2.2M192 32.6h2.2M202.4 30.4v2.2h-1.7M202.9 29.9v1M202.9 31.2v.6M202.9 32.1v1M202.9 31.5h1.1v1.1M202.9 32.6h2.2M202.9 30.4h2.2M203.8 31.2l-.6 .3 .6 .3M80.9 44.6h1.6M81.3 44.8h.9"/>
<path d="M81.7 43.5v1.1M92.7 40.3h2.2M101.4 40.3h2.2M106.8 46.8h2.3M107.1 57.7h1.7M107.5 58h.9M107.9 47.2l.8 .2 .3 .2M107.9 47.2l-.3 .1-.7 .3M107.9 45.7v1.1M107.9 47.2v1.8M107.9 56.6v1.1M110.2 46.8h2.1"/>
<path d="M111.2 47.2l.8 .2 .3 .2M111.2 47.2l-.7 .2-.3 .2M111.2 45.7v1.1M111.2 47.2v1.8M117.8 40.3h2.2M117.8 42.5h2.2M117.8 44.6h2.2M117.8 46.8h2.2M117.8 49h2.2M117.8 51.2h2.2M134.2 40.3h2.2M134.2 42.5h2.2"/>
<path d="M134.2 44.6h2.2M134.2 46.8h2.2M134.2 49h2.2M134.2 51.2h2.2M162.6 55.5h2.1M163.7 56h.3l.7 .3M163.7 56l-.8 .1-.3 .2M163.7 54.4v1.1M163.7 56v1.7M171.3 53.3v1.1l.4 .2-.8 .2 .8 .3-.8 .3 .8 .3-.8 .2 .8 .3-.8 .3 .4 .1v1.1M176.7 53.3v1.1l.5 .2-.9 .2 .9 .3-.9 .3 .9 .3-.9 .2 .9 .3-.9 .3 .4 .1v1.1M181.1 58.8h2.2"/>
<path d="M183.3 55.8l8.7 5.2-8.7 5.2zM186.6 55.5v2.2M192.3 44.6h1.6M192.7 44.8h.9M193.1 43.5v1.1M202.4 58.8v2.2h-1.7M202.9 58.3v1M202.9 59.6v.6M202.9 59.9h1.1v1.1M202.9 58.8h2.2M203.8 59.6l-.6 .3 .6 .3M139.6 61v1.1l.4 .1-.8 .3 .8 .2-.8 .3 .8 .3-.8 .3 .8 .2-.8 .3 .4 .2v1.1"/>
<path d="M139.6 67.6v1.1h.4l-.8 .3 .8 .3-.8 .3 .8 .2-.8 .3 .8 .3-.8 .3 .4 .1v1.1M144 61v1.1l.4 .1-.8 .3 .8 .2-.8 .3 .8 .3-.8 .3 .8 .2-.8 .3 .4 .2v1.1M144 67.6v1.1h.4l-.8 .3 .8 .3-.8 .3 .8 .2-.8 .3 .8 .3-.8 .3 .4 .1v1.1M176.7 65.4v1.1l.5 .1-.9 .2 .9 .3-.9 .3 .9 .2-.9 .3 .9 .3-.9 .3 .4 .2v1M181.1 63.2h2.2M186.6 64.3v2.2M192 61h2.2M192.3 73h1.6M192.7 73.2h.9M193.1 71.9v1.1M202.9 61h2.2M202.9 60.5v1"/>
<path d="M81.7 87.2a1.1 1.1 0 0 0 1.1 1.1 1.1 1.1 0 0 0 1.1-1.1M82.8 88.3v2.2M217.5 98.8v.9M217.7 98.4v1.6M217.7 99.2h1.1M221.3 97.7v.9M221.5 97.3v1.6M221.5 98.1h1.1M224.2 98.1h2.2M224.2 99.2h2.2M224.2 89.4h2.2M224.2 90.5h2.2"/>
<path d="M224.2 91.6h2.2M224.2 92.7h2.2M224.2 93.8h2.2M224.2 94.8h2.2M224.2 95.9h2.2M224.2 97h2.2M226.4 88.3h5.5v29.5h-5.5zM231.9 98.1h2.2M231.9 99.2h2.2M231.9 89.4h2.2M231.9 90.5h2.2M231.9 91.6h2.2"/>
<path d="M231.9 92.7h2.2M231.9 93.8h2.2M231.9 94.8h2.2M231.9 95.9h2.2M231.9 97h2.2M207.6 118.9h1.6M207.9 119.1h1M208.4 117.8v1.1M224.2 100.3h2.2M224.2 101.4h2.2M224.2 102.5h2.2M224.2 103.6h2.2"/>
<path d="M224.2 104.7h2.2M224.2 105.7h2.2M224.2 106.8h2.2M224.2 107.9h2.2M224.2 109.1h2.2M224.2 110.2h2.2M224.2 111.2h2.2M224.2 112.3h2.2M224.2 113.4h2.2M224.2 114.5h2.2M224.2 115.6h2.2M224.2 116.7h2.2"/>
<path d="M231.9 100.3h2.2M231.9 101.4h2.2M231.9 102.5h2.2M231.9 103.6h2.2M231.9 104.7h2.2M231.9 105.7h2.2M231.9 106.8h2.2M231.9 107.9h2.2M231.9 109.1h2.2M231.9 110.2h2.2M231.9 111.2h2.2M231.9 112.3h2.2"/>
<path d="M231.9 113.4h2.2M231.9 114.5h2.2M231.9 115.6h2.2M231.9 116.7h2.2M19.5 139.6h2.2M21.7 138.5h10.9v5.5h-10.9zM32.6 139.6h2.2M47.4 127.6h3.2M48.4 127.6l1.1-.6v1.1zM48.8 127.2v-.2h-.4v1.1h-.3v-.1M52.8 136.3h3.3M53.9 135.8l1.1 .5-1.1 .6z"/>
<path d="M55.3 135.9v-.1h-.3v1.1h-.3v-.1M177.8 136.3h2.2M177.8 138.5h2.2M177.8 134.2h2.2M180 133.1h10.9v8.7h-10.9zM190.9 136.3h2.2M190.9 138.5h2.2M190.9 134.2h2.2M197.5 139.6v1.1M200.7 127.6h1.1l.2-.4 .2 .8 .3-.8 .3 .8 .3-.8 .2 .8 .3-.8 .3 .8 .1-.4h1.1M200.7 136.3h1.1M200.7 128.7v1.1l.5 .1-.9 .3 .9 .2-.9 .3 .9 .3-.9 .3 .9 .2-.9 .3 .4 .2v1.1"/>
<path d="M201.8 135.3v2.1M202.6 135.3l-.3 .6v.4M204 136.3h-1.7l.1 .8 .2 .3M205.1 128.7v1.1l.5 .1-.9 .3 .9 .2-.9 .3 .9 .3-.9 .3 .9 .2-.9 .3 .4 .2v1.1M19.5 140.7h2.2M19.5 141.8h2.2M19.5 142.9h2.2M31.8 149.4h1.6M32.1 149.6h1M32.6 148.3v1.1M32.6 140.7h2.2M32.6 141.8h2.2"/>
<path d="M32.6 142.9h2.2M43.8 144.5h.1v.4h-.1zM44.6 144v1.1M44.6 146.2v1M45.2 154.9h3.2M46.3 154.9l1.1-.6v1.1zM46.6 154.5v-.2h-.3v1.1h-.4v-.1M122.8 157.1h.9M123.2 157.6h2.2M123.2 154.9v2.2M124 157.1h.7M124 156.8l.3-.6 .4 .6"/>
<path d="M124.9 157.1h1M125.4 156h-1.1v1.1M125.4 154.9v2.2M125.4 157.6v1.7M128.7 154.9v1.1l.4 .1-.8 .3 .8 .2-.8 .3 .8 .3-.8 .2 .8 .3-.8 .3 .4 .2v1.1M177.8 140.7h2.2M190.9 140.7h2.2M193.4 145.1h1.6M193.8 145.3h.9M194.2 144v1.1M196.4 140.7h2.2M197.5 141.1l.4 .1 .6 .3"/>
<path d="M197.5 141.1l-.4 .1-.7 .3M197.5 141.1v1.8M213.1 151.6h1.6M213.4 151.8h.9M213.9 150.5v1.1M223.7 154.9h2.2M223.7 148.3h2.2M223.7 149.4h2.2M223.7 150.5h2.2M223.7 151.6h2.2M223.7 152.7h2.2M223.7 153.8h2.2"/>
<path d="M223.7 156h2.2M223.7 157.1h2.2M223.7 158.2h2.2M223.7 159.3h2.2M225.9 147.2h5.5v29.5h-5.5zM231.4 154.9h2.1M231.4 148.3h2.1M231.4 149.4h2.1M231.4 150.5h2.1M231.4 151.6h2.1M231.4 152.7h2.1M231.4 153.8h2.1"/>
<path d="M231.4 156h2.1M231.4 157.1h2.1M231.4 158.2h2.1M231.4 159.3h2.1M277.5 154.9h1.6M277.8 155.1h1M278.3 153.8v1.1M19.5 166.9h2.2M19.5 168h2.2M19.5 169.1h2.2M19.5 170.2h2.2M21.7 165.8h10.9v5.5h-10.9z"/>
<path d="M32.6 166.9h2.2M32.6 168h2.2M32.6 169.1h2.2M32.6 170.2h2.2M52.8 163.6h3.3M53.9 163.1l1.1 .5-1.1 .6zM55.3 163.2v-.1h-.3v1.1h-.3v-.2M73 175.6h2.2M74.1 176.1h.4l.7 .3M74.1 176.1l-.7 .1-.4 .2M74.1 174.5v1.1M74.1 176.1v1.7"/>
<path d="M77.4 175.6h2.2M77.4 177.8h2.2M79.6 174.5h6.5v6.6h-6.5zM86.1 175.6h2.2M92.7 176.7h2.2M93.8 177.2h.3l.7 .3M93.8 177.2h-.4l-.7 .3M93.8 175.6v1.1M93.8 177.2v1.7M98.1 173.4v1.1l.5 .2-.9 .2 .9 .3-.9 .3 .9 .2-.9 .3 .9 .3-.9 .3 .4 .1v1.1M98.1 178.9v1.1l.5 .1-.9 .3 .9 .2-.9 .3 .9 .3-.9 .3 .9 .2-.9 .3 .4 .2v1.1M101.4 173.4v1.1l.5 .2-.9 .2 .9 .3-.9 .3 .9 .2-.9 .3 .9 .3-.9 .3 .4 .1v1.1"/>
<path d="M107.9 178.9h2.3M107.9 177.8h2.3M110.2 176.7h6.5v6.6h-6.5zM116.7 178.9h2.2M116.7 177.8h2.2M120 163.6h1.1l.1-.4 .3 .8 .2-.8 .3 .8 .3-.8 .2 .8 .3-.8 .3 .8 .1-.4h1.1M129.8 174.5v1.1l.4 .1-.8 .3 .8 .3-.8 .3 .8 .2-.8 .3 .8 .3-.8 .3 .4 .1v1.1M157.1 172.9h2.2M158.2 173.4l.7 .1 .4 .2M158.2 173.4h-.4l-.7 .3M158.2 171.8v1.1M158.2 173.4v1.7"/>
<path d="M161.5 172.9h2.2M162.6 173.4l.7 .1 .3 .2M162.6 173.4h-.4l-.7 .3M162.6 171.8v1.1M162.6 173.4v1.7M173.5 171.3h2.1M173.5 173.4h2.1M173.5 175.6h2.1M175.6 170.2h6.6v6.5h-6.6zM182.2 171.3h2.2M182.2 175.6h2.2M184.4 174.2l.3-.2 .8-.1v1.7"/>
<path d="M184.4 173.4h2.2M185.5 173.9l.7 .1 .4 .2M185.5 172.3v1.1M215.8 177.8h1.6M216.1 178.1h1M216.6 176.7v1.1M223.7 163.6h2.2M223.7 171.3h2.2M223.7 165.8h2.2M223.7 166.9h2.2M223.7 168h2.2M223.7 169.1h2.2"/>
<path d="M223.7 170.2h2.2M223.7 160.4h2.2M223.7 161.5h2.2M223.7 162.5h2.2M223.7 164.7h2.2M223.7 172.3h2.2M223.7 173.4h2.2M223.7 174.5h2.2M223.7 175.6h2.2M231.4 163.6h2.1M231.4 171.3h2.1M231.4 165.8h2.1"/>
<path d="M231.4 166.9h2.1M231.4 168h2.1M231.4 169.1h2.1M231.4 170.2h2.1M231.4 160.4h2.1M231.4 161.5h2.1M231.4 162.5h2.1M231.4 164.7h2.1M231.4 172.3h2.1M231.4 173.4h2.1M231.4 174.5h2.1M231.4 175.6h2.1"/>
<path d="M77.4 180h2.2M86.1 180h2.2M86.4 187.7h1.6M86.7 187.9h1M87.2 186.6v1.1M101.4 180v1.1l.5 .1-.9 .3 .9 .2-.9 .3 .9 .3-.9 .3 .9 .2-.9 .3 .4 .2v1.1M107.9 180h2.3M107.9 181.1h2.3M107.9 182.2h2.3M116.7 180h2.2M116.7 181.1h2.2M116.7 182.2h2.2"/>
<path d="M171.6 184.4h1.6M171.9 184.6h.9M172.4 183.3v1.1"/>
</g>
<path d="M13 160.4h-1.1v8.7h7.6M34.8 170.2h13.1" fill="none" stroke="#008000" stroke-width=".13"/>
<circle cx="11.9" cy="169.1" r=".21" fill="#008000"/>
<g fill="none" stroke="#008000" stroke-width=".13">
<path d="M6.4 168h13.1M7.5 168v3.3"/>
<circle cx="11.9" cy="169.1" r=".21"/>
</g>
<circle cx="7.5" cy="168" r=".21" fill="#008000"/>
<g fill="none" stroke="#008000" stroke-width=".13">
<path d="M13 133.1h-1.1v8.7h7.6M34.8 140.7h5.5v3.3"/>
<circle cx="7.5" cy="168" r=".21"/>
</g>
<circle cx="11.9" cy="141.8" r=".21" fill="#008000"/>
<g fill="none" stroke="#008000" stroke-width=".13">
<path d="M2 140.7v3.3M6.4 140.7h13.1M7.5 140.7v3.3"/>
<circle cx="11.9" cy="141.8" r=".21"/>
</g>
<circle cx="7.5" cy="140.7" r=".21" fill="#008000"/>
<g fill="none" stroke="#008000" stroke-width=".13">
<path d="M37 127.6v14.2h-2.2"/>
<circle cx="7.5" cy="140.7" r=".21"/>
</g>
<circle cx="37" cy="136.3" r=".21" fill="#008000"/>
<g fill="none" stroke="#008000" stroke-width=".13">
<path d="M37 136.3h7.6v7.7"/>
<circle cx="37" cy="136.3" r=".21"/>
</g>
<circle cx="44.6" cy="136.3" r=".21" fill="#008000"/>
<g fill="none" stroke="#008000" stroke-width=".13">
<path d="M37 127.6h10.4M35.9 141.8v2.2"/>
<circle cx="44.6" cy="136.3" r=".21"/>
</g>
<circle cx="35.9" cy="141.8" r=".21" fill="#008000"/>
<g fill="none" stroke="#008000" stroke-width=".13">
<path d="M109.1 74.1h-1.2v4.4h31.7M126.5 74.1h1.1v4.4M168 175.6h5.5M233.5 169.1h25.1"/>
<circle cx="35.9" cy="141.8" r=".21"/>
</g>
<circle cx="127.6" cy="78.5" r=".21" fill="#008000"/>
<g fill="none" stroke="#008000" stroke-width=".13">
<path d="M139.6 71.9v6.6h8.7"/>
<circle cx="127.6" cy="78.5" r=".21"/>
</g>
<circle cx="139.6" cy="78.5" r=".21" fill="#008000"/>
<g fill="none" stroke="#008000" stroke-width=".13">
<path d="M107.9 95.9v-4.3h20.8v8.7M109.1 98.1h-5.5v11M109.1 95.9h-7.7v12h-3.3M98.1 106.8v2.3M233.5 148.3h25.1"/>
<circle cx="139.6" cy="78.5" r=".21"/>
</g>
<circle cx="107.9" cy="95.9" r=".21" fill="#008000"/>
<circle cx="107.9" cy="95.9" r=".21" fill="none" stroke="#008000" stroke-width=".13"/>
<circle cx="98.1" cy="107.9" r=".21" fill="#008000"/>
<g fill="none" stroke="#008000" stroke-width=".13">
<path d="M126.5 98.1h7.7v4.4M98.1 113.4v3.3h36.1M126.5 100.3h2.2M126.5 102.5h3.3v14.2"/>
<circle cx="98.1" cy="107.9" r=".21"/>
</g>
<circle cx="129.8" cy="116.7" r=".21" fill="#008000"/>
<g fill="none" stroke="#008000" stroke-width=".13">
<path d="M126.5 95.9h3.3v6.6M134.2 106.8v9.9"/>
<circle cx="129.8" cy="116.7" r=".21"/>
</g>
<circle cx="129.8" cy="102.5" r=".21" fill="#008000"/>
<g fill="none" stroke="#008000" stroke-width=".13">
<path d="M134.2 116.7v1.1"/>
<circle cx="129.8" cy="102.5" r=".21"/>
</g>
<circle cx="134.2" cy="116.7" r=".21" fill="#008000"/>
<g fill="none" stroke="#008000" stroke-width=".13">
<path d="M103.6 113.4v3.3"/>
<circle cx="134.2" cy="116.7" r=".21"/>
</g>
<circle cx="103.6" cy="116.7" r=".21" fill="#008000"/>
<g fill="none" stroke="#008000" stroke-width=".13">
<path d="M126.5 71.9h3.3v14.2M98.1 82.8v3.3h36.1"/>
<circle cx="103.6" cy="116.7" r=".21"/>
</g>
<circle cx="129.8" cy="86.1" r=".21" fill="#008000"/>
<g fill="none" stroke="#008000" stroke-width=".13">
<path d="M126.5 65.4h3.3v6.5M134.2 76.3v9.8"/>
<circle cx="129.8" cy="86.1" r=".21"/>
</g>
<circle cx="129.8" cy="71.9" r=".21" fill="#008000"/>
<g fill="none" stroke="#008000" stroke-width=".13">
<path d="M134.2 86.1v2.2"/>
<circle cx="129.8" cy="71.9" r=".21"/>
</g>
<circle cx="134.2" cy="86.1" r=".21" fill="#008000"/>
<g fill="none" stroke="#008000" stroke-width=".13">
<path d="M103.6 82.8v3.3"/>
<circle cx="134.2" cy="86.1" r=".21"/>
</g>
<circle cx="103.6" cy="86.1" r=".21" fill="#008000"/>
<g fill="none" stroke="#008000" stroke-width=".13">
<path d="M205.1 32.6h2.2v9.9h-14.2v1"/>
<circle cx="103.6" cy="86.1" r=".21"/>
</g>
<circle cx="193.1" cy="42.5" r=".21" fill="#008000"/>
<g fill="none" stroke="#008000" stroke-width=".13">
<path d="M186.6 38.1v4.4"/>
<circle cx="193.1" cy="42.5" r=".21"/>
</g>
<circle cx="186.6" cy="42.5" r=".21" fill="#008000"/>
<g fill="none" stroke="#008000" stroke-width=".13">
<path d="M176.7 41.4v1.1h16.4"/>
<circle cx="186.6" cy="42.5" r=".21"/>
</g>
<circle cx="176.7" cy="42.5" r=".21" fill="#008000"/>
<g fill="none" stroke="#008000" stroke-width=".13">
<path d="M163.7 29.3v13.2h13M163.7 57.7v13.1M205.1 61h2.2v9.8h-14.2"/>
<circle cx="176.7" cy="42.5" r=".21"/>
</g>
<circle cx="193.1" cy="70.8" r=".21" fill="#008000"/>
<g fill="none" stroke="#008000" stroke-width=".13">
<path d="M186.6 66.5v4.3h6.5v1.1"/>
<circle cx="193.1" cy="70.8" r=".21"/>
</g>
<circle cx="186.6" cy="70.8" r=".21" fill="#008000"/>
<g fill="none" stroke="#008000" stroke-width=".13">
<path d="M163.7 70.8h22.9M176.7 69.7v1.1"/>
<circle cx="186.6" cy="70.8" r=".21"/>
</g>
<circle cx="176.7" cy="70.8" r=".21" fill="#008000"/>
<g fill="none" stroke="#008000" stroke-width=".13">
<path d="M222.6 98.1h1.6M223.7 106.8h.5"/>
<circle cx="176.7" cy="70.8" r=".21"/>
</g>
<circle cx="223.7" cy="98.1" r=".21" fill="#008000"/>
<g fill="none" stroke="#008000" stroke-width=".13">
<path d="M218.8 99.2h5.4M223.7 98.1v8.7M233.5 152.7h44.8v1.1M2 174.5v1.1h5.5v-1.1"/>
<circle cx="223.7" cy="98.1" r=".21"/>
</g>
<circle cx="7.5" cy="175.6" r=".21" fill="#008000"/>
<g fill="none" stroke="#008000" stroke-width=".13">
<path d="M11.9 173.4v2.2h-4.4"/>
<circle cx="7.5" cy="175.6" r=".21"/>
</g>
<circle cx="11.9" cy="175.6" r=".21" fill="#008000"/>
<g fill="none" stroke="#008000" stroke-width=".13">
<path d="M11.9 175.6h4.4"/>
<circle cx="11.9" cy="175.6" r=".21"/>
</g>
<circle cx="16.3" cy="175.6" r=".21" fill="#008000"/>
<g fill="none" stroke="#008000" stroke-width=".13">
<path d="M19.5 170.2h-3.2v5.4h19.6v-1.1"/>
<circle cx="16.3" cy="175.6" r=".21"/>
</g>
<circle cx="35.9" cy="175.6" r=".21" fill="#008000"/>
<g fill="none" stroke="#008000" stroke-width=".13">
<path d="M40.3 174.5v1.1h-4.4"/>
<circle cx="35.9" cy="175.6" r=".21"/>
</g>
<circle cx="40.3" cy="175.6" r=".21" fill="#008000"/>
<g fill="none" stroke="#008000" stroke-width=".13">
<path d="M44.6 174.5v1.1h-4.3"/>
<circle cx="40.3" cy="175.6" r=".21"/>
</g>
<circle cx="44.6" cy="175.6" r=".21" fill="#008000"/>
<g fill="none" stroke="#008000" stroke-width=".13">
<path d="M44.6 175.6h1.1v2.2"/>
<circle cx="44.6" cy="175.6" r=".21"/>
</g>
<circle cx="45.7" cy="175.6" r=".21" fill="#008000"/>
<g fill="none" stroke="#008000" stroke-width=".13">
<path d="M52.3 170.2v5.4h-6.6"/>
<circle cx="45.7" cy="175.6" r=".21"/>
</g>
<circle cx="52.3" cy="175.6" r=".21" fill="#008000"/>
<g fill="none" stroke="#008000" stroke-width=".13">
<path d="M56.6 171.3v4.3h-4.3M107.9 182.2h-2.1v2.2h15.3v-2.2h-2.2"/>
<circle cx="52.3" cy="175.6" r=".21"/>
</g>
<circle cx="105.8" cy="184.4" r=".21" fill="#008000"/>
<g fill="none" stroke="#008000" stroke-width=".13">
<path d="M101.4 184.4h4.4"/>
<circle cx="105.8" cy="184.4" r=".21"/>
</g>
<circle cx="101.4" cy="184.4" r=".21" fill="#008000"/>
<g fill="none" stroke="#008000" stroke-width=".13">
<path d="M98.1 183.3v1.1h3.3"/>
<circle cx="101.4" cy="184.4" r=".21"/>
</g>
<circle cx="98.1" cy="184.4" r=".21" fill="#008000"/>
<g fill="none" stroke="#008000" stroke-width=".13">
<path d="M93.8 178.9v5.5h4.3"/>
<circle cx="98.1" cy="184.4" r=".21"/>
</g>
<circle cx="93.8" cy="184.4" r=".21" fill="#008000"/>
<g fill="none" stroke="#008000" stroke-width=".13">
<path d="M93.8 184.4h-6.6v2.2"/>
<circle cx="93.8" cy="184.4" r=".21"/>
</g>
<circle cx="87.2" cy="184.4" r=".21" fill="#008000"/>
<g fill="none" stroke="#008000" stroke-width=".13">
<path d="M74.1 177.8h3.3M74.1 184.4h13.1"/>
<circle cx="87.2" cy="184.4" r=".21"/>
</g>
<circle cx="74.1" cy="177.8" r=".21" fill="#008000"/>
<g fill="none" stroke="#008000" stroke-width=".13">
<path d="M193.1 138.5h1.1v5.5M223.7 149.4h-9.8v1.1M74.1 177.8v6.6"/>
<circle cx="74.1" cy="177.8" r=".21"/>
</g>
<circle cx="194.2" cy="142.9" r=".21" fill="#008000"/>
<g fill="none" stroke="#008000" stroke-width=".13">
<path d="M177.8 134.2h-1.1v2.1"/>
<circle cx="194.2" cy="142.9" r=".21"/>
</g>
<circle cx="176.7" cy="136.3" r=".21" fill="#008000"/>
<g fill="none" stroke="#008000" stroke-width=".13">
<path d="M92.7 38.1h-7.7v3.8h-7.6v-1.6M81.7 40.3v3.2M224.2 116.7h-15.8v1.1M177.8 136.3h-1.1v6.6h20.8"/>
<circle cx="176.7" cy="136.3" r=".21"/>
</g>
<circle cx="81.7" cy="41.9" r=".21" fill="#008000"/>
<circle cx="81.7" cy="41.9" r=".21" fill="none" stroke="#008000" stroke-width=".13"/>
<circle cx="85" cy="41.9" r=".21" fill="#008000"/>
<g fill="none" stroke="#008000" stroke-width=".13">
<path d="M172.4 173.4h1.1M185.5 175.6v5.5h-25.1M172.4 181.1v2.2"/>
<circle cx="85" cy="41.9" r=".21"/>
</g>
<circle cx="172.4" cy="181.1" r=".21" fill="#008000"/>
<g fill="none" stroke="#008000" stroke-width=".13">
<path d="M158.2 175.1v6h2.2M162.6 175.1v6M172.4 173.4v7.7"/>
<circle cx="172.4" cy="181.1" r=".21"/>
</g>
<circle cx="162.6" cy="181.1" r=".21" fill="#008000"/>
<g fill="none" stroke="#008000" stroke-width=".13">
<path d="M11.9 146.2v2.1M56.6 144v4.3h-54.6"/>
<circle cx="162.6" cy="181.1" r=".21"/>
</g>
<circle cx="11.9" cy="148.3" r=".21" fill="#008000"/>
<g fill="none" stroke="#008000" stroke-width=".13">
<path d="M16.3 139.6v3.3"/>
<circle cx="11.9" cy="148.3" r=".21"/>
</g>
<circle cx="16.3" cy="148.3" r=".21" fill="#008000"/>
<g fill="none" stroke="#008000" stroke-width=".13">
<path d="M16.3 142.9v5.4M40.3 147.2v1.1"/>
<circle cx="16.3" cy="148.3" r=".21"/>
</g>
<circle cx="40.3" cy="148.3" r=".21" fill="#008000"/>
<g fill="none" stroke="#008000" stroke-width=".13">
<path d="M52.3 142.9v5.4"/>
<circle cx="40.3" cy="148.3" r=".21"/>
</g>
<circle cx="52.3" cy="148.3" r=".21" fill="#008000"/>
<g fill="none" stroke="#008000" stroke-width=".13">
<path d="M2 147.2v1.1M7.5 147.2v1.1"/>
<circle cx="52.3" cy="148.3" r=".21"/>
</g>
<circle cx="7.5" cy="148.3" r=".21" fill="#008000"/>
<g fill="none" stroke="#008000" stroke-width=".13">
<path d="M35.9 147.2v1.1"/>
<circle cx="7.5" cy="148.3" r=".21"/>
</g>
<circle cx="35.9" cy="148.3" r=".21" fill="#008000"/>
<g fill="none" stroke="#008000" stroke-width=".13">
<path d="M44.6 147.2v1.1"/>
<circle cx="35.9" cy="148.3" r=".21"/>
</g>
<circle cx="44.6" cy="148.3" r=".21" fill="#008000"/>
<g fill="none" stroke="#008000" stroke-width=".13">
<path d="M16.3 139.6h3.2M16.3 142.9h3.2"/>
<circle cx="44.6" cy="148.3" r=".21"/>
</g>
<circle cx="16.3" cy="142.9" r=".21" fill="#008000"/>
<circle cx="16.3" cy="142.9" r=".21" fill="none" stroke="#008000" stroke-width=".13"/>
<circle cx="32.6" cy="148.3" r=".21" fill="#008000"/>
<g fill="none" stroke="#008000" stroke-width=".13">
<path d="M115.6 31.5h2.2M115.6 35.9h2.2M115.6 38.1h2.2M136.4 31.5h1.1v-3.3h-21.9v26.2h-7.7v-5.4M111.2 49v5.4"/>
<circle cx="32.6" cy="148.3" r=".21"/>
</g>
<circle cx="115.6" cy="54.4" r=".21" fill="#008000"/>
<circle cx="115.6" cy="54.4" r=".21" fill="none" stroke="#008000" stroke-width=".13"/>
<circle cx="111.2" cy="54.4" r=".21" fill="#008000"/>
<circle cx="111.2" cy="54.4" r=".21" fill="none" stroke="#008000" stroke-width=".13"/>
<circle cx="115.6" cy="31.5" r=".21" fill="#008000"/>
<circle cx="115.6" cy="31.5" r=".21" fill="none" stroke="#008000" stroke-width=".13"/>
<circle cx="115.6" cy="35.9" r=".21" fill="#008000"/>
<circle cx="115.6" cy="35.9" r=".21" fill="none" stroke="#008000" stroke-width=".13"/>
<circle cx="115.6" cy="38.1" r=".21" fill="#008000"/>
<g fill="none" stroke="#008000" stroke-width=".13">
<path d="M144 38.1h3.3v16.3h-31.7M136.4 40.3h7.6v2.2"/>
<circle cx="115.6" cy="38.1" r=".21"/>
</g>
<circle cx="144" cy="54.4" r=".21" fill="#008000"/>
<g fill="none" stroke="#008000" stroke-width=".13">
<path d="M136.4 42.5h7.6v11.9"/>
<circle cx="144" cy="54.4" r=".21"/>
</g>
<circle cx="144" cy="42.5" r=".21" fill="#008000"/>
<g fill="none" stroke="#008000" stroke-width=".13">
<path d="M107.9 54.4v2.2"/>
<circle cx="144" cy="42.5" r=".21"/>
</g>
<circle cx="107.9" cy="54.4" r=".21" fill="#008000"/>
<g fill="none" stroke="#008000" stroke-width=".13">
<path d="M139.6 54.4v6.6"/>
<circle cx="107.9" cy="54.4" r=".21"/>
</g>
<circle cx="139.6" cy="54.4" r=".21" fill="#008000"/>
<g fill="none" stroke="#008000" stroke-width=".13">
<path d="M117.8 49v5.4M144 54.4v6.6"/>
<circle cx="139.6" cy="54.4" r=".21"/>
</g>
<circle cx="117.8" cy="51.2" r=".21" fill="#008000"/>
<circle cx="117.8" cy="51.2" r=".21" fill="none" stroke="#008000" stroke-width=".13"/>
<circle cx="117.8" cy="54.4" r=".21" fill="#008000"/>
<g fill="none" stroke="#008000" stroke-width=".13">
<path d="M117.8 46.8v2.2"/>
<circle cx="117.8" cy="54.4" r=".21"/>
</g>
<circle cx="117.8" cy="49" r=".21" fill="#008000"/>
<g fill="none" stroke="#008000" stroke-width=".13">
<path d="M117.8 44.6v2.2M216.6 174.5h7.1M216.6 172.3h7.1M216.6 170.2h7.1M223.7 168h-7.1v8.7"/>
<circle cx="117.8" cy="49" r=".21"/>
</g>
<circle cx="216.6" cy="170.2" r=".21" fill="#008000"/>
<circle cx="216.6" cy="170.2" r=".21" fill="none" stroke="#008000" stroke-width=".13"/>
<circle cx="216.6" cy="172.3" r=".21" fill="#008000"/>
<circle cx="216.6" cy="172.3" r=".21" fill="none" stroke="#008000" stroke-width=".13"/>
<circle cx="216.6" cy="174.5" r=".21" fill="#008000"/>
<g fill="none" stroke="#008000" stroke-width=".13">
<path d="M98.1 76.3v2.2M107.9 65.4v-4.4h20.8v8.7M109.1 67.6h-5.5v10.9M109.1 65.4h-7.7v12h-3.3"/>
<circle cx="216.6" cy="174.5" r=".21"/>
</g>
<circle cx="107.9" cy="65.4" r=".21" fill="#008000"/>
<circle cx="107.9" cy="65.4" r=".21" fill="none" stroke="#008000" stroke-width=".13"/>
<circle cx="98.1" cy="77.4" r=".21" fill="#008000"/>
<g fill="none" stroke="#008000" stroke-width=".13">
<path d="M126.5 69.7h2.2M126.5 67.6h7.7v4.3M109.1 104.7h-1.2v4.4h36.1M126.5 104.7h1.1v4.4"/>
<circle cx="98.1" cy="77.4" r=".21"/>
</g>
<circle cx="127.6" cy="109" r=".21" fill="#008000"/>
<g fill="none" stroke="#008000" stroke-width=".13">
<path d="M144 71.9v37.2h4.3"/>
<circle cx="127.6" cy="109" r=".21"/>
</g>
<circle cx="144" cy="109" r=".21" fill="#008000"/>
<g fill="none" stroke="#008000" stroke-width=".13">
<path d="M223.7 148.3h-13.1v9.9h-66.6v-8.8h4.3M2 168v3.3M34.8 166.9h17.5M51.2 163.6h1.1v4.4M208.4 163.6h15.3"/>
<circle cx="144" cy="109" r=".21"/>
</g>
<circle cx="52.3" cy="166.9" r=".21" fill="#008000"/>
<g fill="none" stroke="#008000" stroke-width=".13">
<path d="M52.3 163.6h.5"/>
<circle cx="52.3" cy="166.9" r=".21"/>
</g>
<circle cx="52.3" cy="163.6" r=".21" fill="#008000"/>
<g fill="none" stroke="#008000" stroke-width=".13">
<path d="M34.8 139.6h17.5M52.3 136.3v4.4"/>
<circle cx="52.3" cy="163.6" r=".21"/>
</g>
<circle cx="52.3" cy="139.6" r=".21" fill="#008000"/>
<g fill="none" stroke="#008000" stroke-width=".13">
<path d="M51.2 136.3h1.6"/>
<circle cx="52.3" cy="139.6" r=".21"/>
</g>
<circle cx="52.3" cy="136.3" r=".21" fill="#008000"/>
<g fill="none" stroke="#008000" stroke-width=".13">
<path d="M56.6 136.3v4.4"/>
<circle cx="52.3" cy="136.3" r=".21"/>
</g>
<circle cx="56.6" cy="136.3" r=".21" fill="#008000"/>
<g fill="none" stroke="#008000" stroke-width=".13">
<path d="M17.3 133.1h39.3v3.2M56.1 136.3h9.3M233.5 159.3h25.1"/>
<circle cx="56.6" cy="136.3" r=".21"/>
</g>
<circle cx="241.2" cy="159.3" r=".21" fill="#008000"/>
<g fill="none" stroke="#008000" stroke-width=".13">
<path d="M224.2 105.7h-8.1v59M216.1 142.9h34.9v20.7M241.2 159.3v1.1h-7.7"/>
<circle cx="241.2" cy="159.3" r=".21"/>
</g>
<circle cx="216.1" cy="142.9" r=".21" fill="#008000"/>
<g fill="none" stroke="#008000" stroke-width=".13">
<path d="M223.7 164.7h-7.6v1.1h7.6"/>
<circle cx="216.1" cy="142.9" r=".21"/>
</g>
<circle cx="216.1" cy="164.7" r=".21" fill="#008000"/>
<g fill="none" stroke="#008000" stroke-width=".13">
<path d="M150.5 153.8h12.1M233.5 163.6h17.5"/>
<circle cx="216.1" cy="164.7" r=".21"/>
</g>
<circle cx="156" cy="153.8" r=".21" fill="#008000"/>
<g fill="none" stroke="#008000" stroke-width=".13">
<path d="M50.6 127.6h14.8M193.1 134.2h12M205.1 133.1v3.2h-1.1M34.8 142.9h13.1M233.5 168h25.1"/>
<circle cx="156" cy="153.8" r=".21"/>
</g>
<circle cx="205.1" cy="134.2" r=".21" fill="#008000"/>
<g fill="none" stroke="#008000" stroke-width=".13">
<path d="M200.7 133.1v3.2"/>
<circle cx="205.1" cy="134.2" r=".21"/>
</g>
<circle cx="200.7" cy="136.3" r=".21" fill="#008000"/>
<g fill="none" stroke="#008000" stroke-width=".13">
<path d="M136.4 35.9h9.8M136.4 33.7h9.8M234.1 98.1h14.7M234.1 99.2h14.7M175.6 138.5h2.2M193.1 136.3h7.6M174.5 140.7h3.3M233.5 156h25.1M241.2 156v2.2h-7.7"/>
<circle cx="200.7" cy="136.3" r=".21"/>
</g>
<circle cx="241.2" cy="156" r=".21" fill="#008000"/>
<g fill="none" stroke="#008000" stroke-width=".13">
<path d="M184.4 171.3h9.8"/>
<circle cx="241.2" cy="156" r=".21"/>
</g>
<circle cx="185.5" cy="171.3" r=".21" fill="#008000"/>
<g fill="none" stroke="#008000" stroke-width=".13">
<path d="M136.4 46.8h13v12M171.3 57.7v1.1M233.5 151.6h25.1M185.5 171.3v1"/>
<circle cx="185.5" cy="171.3" r=".21"/>
</g>
<circle cx="171.3" cy="58.8" r=".21" fill="#008000"/>
<g fill="none" stroke="#008000" stroke-width=".13">
<path d="M149.4 58.8h21.9v4.4h9.8"/>
<circle cx="171.3" cy="58.8" r=".21"/>
</g>
<circle cx="171.3" cy="63.2" r=".21" fill="#008000"/>
<g fill="none" stroke="#008000" stroke-width=".13">
<path d="M176.7 57.7v7.7M176.7 58.8h4.4M160.4 63.2h10.9"/>
<circle cx="171.3" cy="63.2" r=".21"/>
</g>
<circle cx="176.7" cy="58.8" r=".21" fill="#008000"/>
<g fill="none" stroke="#008000" stroke-width=".13">
<path d="M176.7 30.4h4.4M176.7 29.3v7.7M194.2 32.6h6.5M205.1 30.4h5.5M205.1 58.8h5.5M233.5 150.5h25.1"/>
<circle cx="176.7" cy="58.8" r=".21"/>
</g>
<circle cx="176.7" cy="30.4" r=".21" fill="#008000"/>
<g fill="none" stroke="#008000" stroke-width=".13">
<path d="M171.3 29.3v5.5h9.8M233.5 153.8h25.1"/>
<circle cx="176.7" cy="30.4" r=".21"/>
</g>
<circle cx="171.3" cy="34.8" r=".21" fill="#008000"/>
<g fill="none" stroke="#008000" stroke-width=".13">
<path d="M160.4 34.8h10.9v9.8h-34.9M205.1 127.6v1.1M207.3 161.5v5.4h16.4"/>
<circle cx="171.3" cy="34.8" r=".21"/>
</g>
<circle cx="205.1" cy="127.6" r=".21" fill="#008000"/>
<g fill="none" stroke="#008000" stroke-width=".13">
<path d="M136.4 38.1h3.2M137.5 66.5h2.1M139.6 65.4v2.2M234.1 116.7h.5v1.6h-22.9v9.3h-6.6M207.3 127.6v33.9"/>
<circle cx="205.1" cy="127.6" r=".21"/>
</g>
<circle cx="139.6" cy="66.5" r=".21" fill="#008000"/>
<g fill="none" stroke="#008000" stroke-width=".13">
<path d="M136.4 51.2h1.1v15.3M141.8 49v17.5h2.2M144 65.4v2.2"/>
<circle cx="139.6" cy="66.5" r=".21"/>
</g>
<circle cx="144" cy="66.5" r=".21" fill="#008000"/>
<g fill="none" stroke="#008000" stroke-width=".13">
<path d="M136.4 49h5.4M89.4 175.6h4.4"/>
<circle cx="144" cy="66.5" r=".21"/>
</g>
<circle cx="93.8" cy="175.6" r=".21" fill="#008000"/>
<g fill="none" stroke="#008000" stroke-width=".13">
<path d="M88.3 175.6h1.1M93.8 175.6v-3.3h14.1v5.5M98.1 173.4h7.7v5.5h2.1"/>
<circle cx="93.8" cy="175.6" r=".21"/>
</g>
<circle cx="101.4" cy="173.4" r=".21" fill="#008000"/>
<circle cx="101.4" cy="173.4" r=".21" fill="none" stroke="#008000" stroke-width=".13"/>
<circle cx="98.1" cy="173.4" r=".21" fill="#008000"/>
<g fill="none" stroke="#008000" stroke-width=".13">
<path d="M101.4 177.8v2.2h2.2v1.1h4.3"/>
<circle cx="98.1" cy="173.4" r=".21"/>
</g>
<circle cx="101.4" cy="180" r=".21" fill="#008000"/>
<g fill="none" stroke="#008000" stroke-width=".13">
<path d="M98.1 178.9v-1.1h6.6v2.2h3.2"/>
<circle cx="101.4" cy="180" r=".21"/>
</g>
<circle cx="98.1" cy="177.8" r=".21" fill="#008000"/>
<g fill="none" stroke="#008000" stroke-width=".13">
<path d="M16.3 166.9h3.2M34.8 168h5.5v3.3M44.6 163.6v7.7"/>
<circle cx="98.1" cy="177.8" r=".21"/>
</g>
<circle cx="44.6" cy="163.6" r=".21" fill="#008000"/>
<g fill="none" stroke="#008000" stroke-width=".13">
<path d="M37 163.6v5.5h-2.2"/>
<circle cx="44.6" cy="163.6" r=".21"/>
</g>
<circle cx="37" cy="163.6" r=".21" fill="#008000"/>
<g fill="none" stroke="#008000" stroke-width=".13">
<path d="M35.9 169.1v2.2M37 163.6h7.6"/>
<circle cx="37" cy="163.6" r=".21"/>
</g>
<circle cx="35.9" cy="169.1" r=".21" fill="#008000"/>
<g fill="none" stroke="#008000" stroke-width=".13">
<path d="M45.2 154.9h-8.2v8.7h-20.7v3.3M48.4 154.9h74.8M128.7 159.3h-3.3v21.8"/>
<circle cx="35.9" cy="169.1" r=".21"/>
</g>
<circle cx="125.4" cy="159.3" r=".21" fill="#008000"/>
<g fill="none" stroke="#008000" stroke-width=".13">
<path d="M234.1 107.9h14.7M193.1 129.8h4.4M133.1 173.4h-3.3v1.1M118.9 181.1h6.5"/>
<circle cx="125.4" cy="159.3" r=".21"/>
</g>
<circle cx="197.5" cy="139.6" r=".21" fill="#008000"/>
<g fill="none" stroke="#008000" stroke-width=".13">
<path d="M197.5 129.8v9.8h-2.2v1.1h-2.2M120 163.6v14.2h-1.1"/>
<circle cx="197.5" cy="139.6" r=".21"/>
</g>
<circle cx="120" cy="163.6" r=".21" fill="#008000"/>
<g fill="none" stroke="#008000" stroke-width=".13">
<path d="M56.6 163.6v4.4"/>
<circle cx="120" cy="163.6" r=".21"/>
</g>
<circle cx="56.6" cy="163.6" r=".21" fill="#008000"/>
<g fill="none" stroke="#008000" stroke-width=".13">
<path d="M255.4 146.2v3.2h-21.9M17.3 160.4h39.3v3.2M56.1 163.6h63.9"/>
<circle cx="56.6" cy="163.6" r=".21"/>
</g>
<circle cx="156" cy="127.6" r=".21" fill="#008000"/>
<g fill="none" stroke="#008000" stroke-width=".13">
<path d="M156 127.6v21.8"/>
<circle cx="156" cy="127.6" r=".21"/>
</g>
<circle cx="156" cy="149.4" r=".21" fill="#008000"/>
<circle cx="156" cy="149.4" r=".21" fill="none" stroke="#008000" stroke-width=".13"/>
<circle cx="156" cy="149.4" r=".21" fill="#008000"/>
<g fill="none" stroke="#008000" stroke-width=".13">
<path d="M200.7 127.6v1.1M150.5 149.4h5.5"/>
<circle cx="156" cy="149.4" r=".21"/>
</g>
<circle cx="200.7" cy="127.6" r=".21" fill="#008000"/>
<g fill="none" stroke="#008000" stroke-width=".13">
<path d="M70.8 127.6h66.1v27.3h-11.5"/>
<circle cx="200.7" cy="127.6" r=".21"/>
</g>
<circle cx="136.9" cy="127.6" r=".21" fill="#008000"/>
<g fill="none" stroke="#008000" stroke-width=".13">
<path d="M67.6 127.6h3.2M136.9 127.6h19.1"/>
<circle cx="136.9" cy="127.6" r=".21"/>
</g>
<circle cx="70.8" cy="127.6" r=".21" fill="#008000"/>
<circle cx="70.8" cy="127.6" r=".21" fill="none" stroke="#008000" stroke-width=".13"/>
<circle cx="156" cy="149.4" r=".21" fill="#008000"/>
<circle cx="156" cy="149.4" r=".21" fill="none" stroke="#008000" stroke-width=".13"/>
<circle cx="128.7" cy="154.9" r=".21" fill="#008000"/>
<g fill="none" stroke="#008000" stroke-width=".13">
<path d="M136.9 154.9v13.6h-59.5"/>
<circle cx="128.7" cy="154.9" r=".21"/>
</g>
<circle cx="136.9" cy="154.9" r=".21" fill="#008000"/>
<g fill="none" stroke="#008000" stroke-width=".13">
<path d="M74.1 174.5v-6h3.3v11.5"/>
<circle cx="136.9" cy="154.9" r=".21"/>
</g>
<circle cx="77.4" cy="168.5" r=".21" fill="#008000"/>
<circle cx="77.4" cy="168.5" r=".21" fill="none" stroke="#008000" stroke-width=".13"/>
<circle cx="77.4" cy="175.6" r=".21" fill="#008000"/>
<g fill="none" stroke="#008000" stroke-width=".13">
<path d="M196.4 127.6h4.3"/>
<circle cx="77.4" cy="175.6" r=".21"/>
</g>
<circle cx="156" cy="127.6" r=".21" fill="#008000"/>
<g fill="none" stroke="#008000" stroke-width=".13">
<path d="M156 127.6h40.4M255.4 149.4h3.2"/>
<circle cx="156" cy="127.6" r=".21"/>
</g>
<circle cx="255.4" cy="149.4" r=".21" fill="#008000"/>
<g fill="none" stroke="#008000" stroke-width=".13">
<path d="M196.4 127.6v-4.4h59v23"/>
<circle cx="255.4" cy="149.4" r=".21"/>
</g>
<circle cx="196.4" cy="127.6" r=".21" fill="#008000"/>
<g fill="none" stroke="#008000" stroke-width=".13">
<path d="M129.8 178.9v1.1M233.5 174.5h25.1"/>
<circle cx="196.4" cy="127.6" r=".21"/>
</g>
<circle cx="129.8" cy="180" r=".21" fill="#008000"/>
<g fill="none" stroke="#008000" stroke-width=".13">
<path d="M176.7 51.2v2.1M186.6 51.2h-15.3v2.1M118.9 180h14.2"/>
<circle cx="129.8" cy="180" r=".21"/>
</g>
<circle cx="176.7" cy="51.2" r=".21" fill="#008000"/>
<g fill="none" stroke="#008000" stroke-width=".13">
<path d="M186.6 51.2v4.3"/>
<circle cx="176.7" cy="51.2" r=".21"/>
</g>
<circle cx="186.6" cy="51.2" r=".21" fill="#008000"/>
<g fill="none" stroke="#008000" stroke-width=".13">
<path d="M176.7 22.8v2.2M186.6 22.8h-15.3v2.2M186.6 51.2h38.2"/>
<circle cx="186.6" cy="51.2" r=".21"/>
</g>
<circle cx="176.7" cy="22.8" r=".21" fill="#008000"/>
<g fill="none" stroke="#008000" stroke-width=".13">
<path d="M186.6 22.8v4.4"/>
<circle cx="176.7" cy="22.8" r=".21"/>
</g>
<circle cx="186.6" cy="22.8" r=".21" fill="#008000"/>
<g fill="none" stroke="#008000" stroke-width=".13">
<path d="M186.6 22.8h42M171.3 51.2h-7.6v3.2"/>
<circle cx="186.6" cy="22.8" r=".21"/>
</g>
<circle cx="171.3" cy="51.2" r=".21" fill="#008000"/>
<g fill="none" stroke="#008000" stroke-width=".13">
<path d="M171.3 22.8h-7.6v3.3"/>
<circle cx="171.3" cy="51.2" r=".21"/>
</g>
<circle cx="171.3" cy="22.8" r=".21" fill="#008000"/>
<g fill="none" stroke="#008000" stroke-width=".13">
<path d="M163.7 22.8h-74.3v13.1h3.3M89.4 40.3h3.3"/>
<circle cx="171.3" cy="22.8" r=".21"/>
</g>
<circle cx="89.4" cy="35.9" r=".21" fill="#008000"/>
<circle cx="89.4" cy="35.9" r=".21" fill="none" stroke="#008000" stroke-width=".13"/>
<circle cx="163.7" cy="22.8" r=".21" fill="#008000"/>
<g fill="none" stroke="#008000" stroke-width=".13">
<path d="M224.8 22.8v28.4"/>
<circle cx="163.7" cy="22.8" r=".21"/>
</g>
<circle cx="224.8" cy="22.8" r=".21" fill="#008000"/>
<g fill="none" stroke="#008000" stroke-width=".13">
<path d="M77.4 37v-1.1h12v4.4M81.7 35.9v1.1"/>
<circle cx="224.8" cy="22.8" r=".21"/>
</g>
<circle cx="81.7" cy="35.9" r=".21" fill="#008000"/>
<g fill="none" stroke="#008000" stroke-width=".13">
<path d="M158.2 171.8v-.5h4.4v.5M233.5 161.5h25.1M233.5 162.5h25.1"/>
<circle cx="81.7" cy="35.9" r=".21"/>
</g>
<circle cx="162.6" cy="171.3" r=".21" fill="#008000"/>
<g fill="none" stroke="#008000" stroke-width=".13">
<path d="M170.2 163.6h29.5M171.3 171.3h2.2"/>
<circle cx="162.6" cy="171.3" r=".21"/>
</g>
<circle cx="124.3" cy="163.6" r=".21" fill="#008000"/>
<g fill="none" stroke="#008000" stroke-width=".13">
<path d="M171.3 163.6h-47v15.3h-5.4"/>
<circle cx="124.3" cy="163.6" r=".21"/>
</g>
<circle cx="171.3" cy="163.6" r=".21" fill="#008000"/>
<g fill="none" stroke="#008000" stroke-width=".13">
<path d="M103.6 33.7v2.2M111.2 42.5v3.2M171.3 163.6v7.7h-8.7"/>
<circle cx="171.3" cy="163.6" r=".21"/>
</g>
<circle cx="111.2" cy="42.5" r=".21" fill="#008000"/>
<g fill="none" stroke="#008000" stroke-width=".13">
<path d="M111.2 42.5h-3.3v3.2M113.4 42.5h4.4"/>
<circle cx="111.2" cy="42.5" r=".21"/>
</g>
<circle cx="113.4" cy="42.5" r=".21" fill="#008000"/>
<g fill="none" stroke="#008000" stroke-width=".13">
<path d="M111.2 42.5h2.2M113.4 40.3h4.4"/>
<circle cx="113.4" cy="42.5" r=".21"/>
</g>
<circle cx="113.4" cy="40.3" r=".21" fill="#008000"/>
<g fill="none" stroke="#008000" stroke-width=".13">
<path d="M117.8 33.7h-4.4v8.8"/>
<circle cx="113.4" cy="40.3" r=".21"/>
</g>
<circle cx="113.4" cy="33.7" r=".21" fill="#008000"/>
<g fill="none" stroke="#008000" stroke-width=".13">
<path d="M103.6 33.7h9.8M194.2 61h6.5M70.8 132h-3.2v2.2h7.6M233.5 166.9h25.1"/>
<circle cx="113.4" cy="33.7" r=".21"/>
</g>
<circle cx="70.8" cy="132" r=".21" fill="#008000"/>
<circle cx="70.8" cy="132" r=".21" fill="none" stroke="#008000" stroke-width=".13"/>
<circle cx="67.6" cy="132" r=".21" fill="#008000"/>
<g fill="none" stroke="#008000" stroke-width=".13">
<path d="M109.1 69.7h-2.3v2.2h2.3M91.6 120h64.4"/>
<circle cx="67.6" cy="132" r=".21"/>
</g>
<circle cx="106.8" cy="71.9" r=".21" fill="#008000"/>
<g fill="none" stroke="#008000" stroke-width=".13">
<path d="M98.1 71.9h8.7"/>
<circle cx="106.8" cy="71.9" r=".21"/>
</g>
<circle cx="98.1" cy="71.9" r=".21" fill="#008000"/>
<g fill="none" stroke="#008000" stroke-width=".13">
<path d="M98.1 71.9h-6.5v30.6"/>
<circle cx="98.1" cy="71.9" r=".21"/>
</g>
<circle cx="91.6" cy="102.5" r=".21" fill="#008000"/>
<g fill="none" stroke="#008000" stroke-width=".13">
<path d="M91.6 102.5v17.5M109.1 100.3h-2.3v2.2h2.3"/>
<circle cx="91.6" cy="102.5" r=".21"/>
</g>
<circle cx="106.8" cy="102.5" r=".21" fill="#008000"/>
<g fill="none" stroke="#008000" stroke-width=".13">
<path d="M91.6 102.5h15.2"/>
<circle cx="106.8" cy="102.5" r=".21"/>
</g>
<circle cx="98.1" cy="102.5" r=".21" fill="#008000"/>
<g fill="none" stroke="#008000" stroke-width=".13">
<path d="M234.1 89.4h1.6v-5.5h-38.2v36.1h-41.5"/>
<circle cx="98.1" cy="102.5" r=".21"/>
</g>
<use href="#words"/>
</svg>
